VERSION 5.8 ;
BUSBITCHARS "[]" ;
DIVIDERCHAR "/" ;
UNITS
    DATABASE MICRONS 1000 ;
END UNITS

VIA ino_data_cache_via1_2_1000_440_1_2_410_410
  VIARULE via1Array ;
  CUTSIZE 0.19 0.19 ;
  LAYERS Metal1 Via1 Metal2 ;
  CUTSPACING 0.22 0.22 ;
  ENCLOSURE 0.05 0.125 0.005 0.05 ;
  ROWCOL 1 2 ;
END ino_data_cache_via1_2_1000_440_1_2_410_410

VIA ino_data_cache_via2_3_1000_440_1_2_410_410
  VIARULE via2Array ;
  CUTSIZE 0.19 0.19 ;
  LAYERS Metal2 Via2 Metal3 ;
  CUTSPACING 0.22 0.22 ;
  ENCLOSURE 0.005 0.05 0.05 0.005 ;
  ROWCOL 1 2 ;
END ino_data_cache_via2_3_1000_440_1_2_410_410

VIA ino_data_cache_via3_4_1000_440_1_2_410_410
  VIARULE via3Array ;
  CUTSIZE 0.19 0.19 ;
  LAYERS Metal3 Via3 Metal4 ;
  CUTSPACING 0.22 0.22 ;
  ENCLOSURE 0.05 0.005 0.2 0.05 ;
  ROWCOL 1 2 ;
END ino_data_cache_via3_4_1000_440_1_2_410_410

VIA ino_data_cache_via4_5_1000_2000_1_1_840_840
  VIARULE viaTop1Array ;
  CUTSIZE 0.42 0.42 ;
  LAYERS Metal4 TopVia1 TopMetal1 ;
  CUTSPACING 0.42 0.42 ;
  ENCLOSURE 0.29 0.1 0.42 0.79 ;
END ino_data_cache_via4_5_1000_2000_1_1_840_840

VIA ino_data_cache_via4_5_2810_2000_1_2_840_840
  VIARULE viaTop1Array ;
  CUTSIZE 0.42 0.42 ;
  LAYERS Metal4 TopVia1 TopMetal1 ;
  CUTSPACING 0.42 0.42 ;
  ENCLOSURE 0.775 0.79 0.42 0.79 ;
  ROWCOL 1 2 ;
END ino_data_cache_via4_5_2810_2000_1_2_840_840

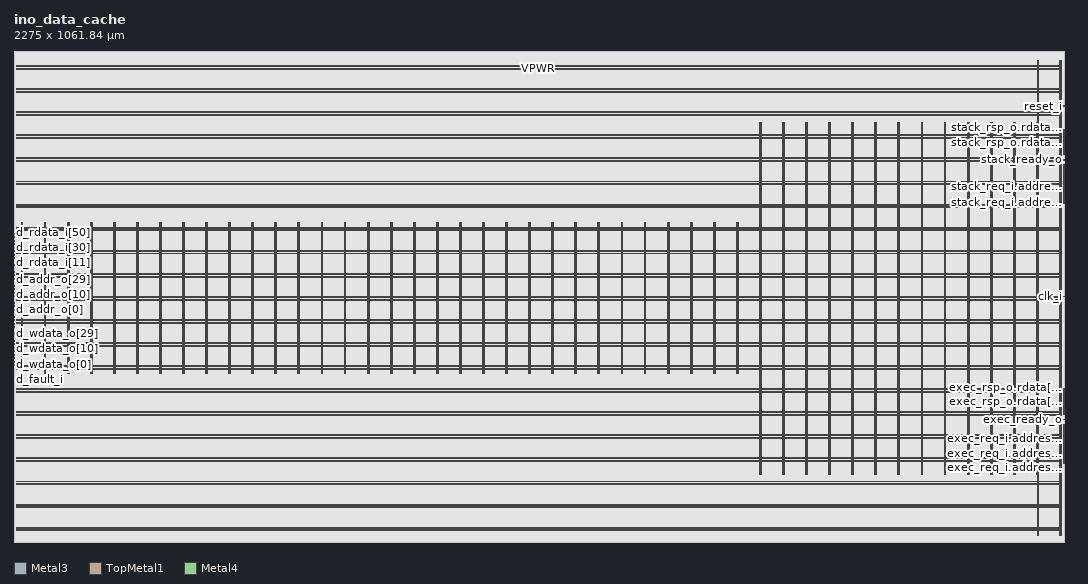
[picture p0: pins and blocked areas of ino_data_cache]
MACRO ino_data_cache
  FOREIGN ino_data_cache 0 0 ;
  CLASS BLOCK ;
  SIZE 2275 BY 1061.84 ;
  PIN clk_i
    DIRECTION INPUT ;
    USE SIGNAL ;
    PORT
      LAYER Metal3 ;
        RECT  2274.6 531.94 2275 532.34 ;
    END
  END clk_i
  PIN d_addr_o[0]
    DIRECTION OUTPUT ;
    USE SIGNAL ;
    PORT
      LAYER Metal3 ;
        RECT  0 502.54 0.4 502.94 ;
    END
  END d_addr_o[0]
  PIN d_addr_o[10]
    DIRECTION OUTPUT ;
    USE SIGNAL ;
    PORT
      LAYER Metal3 ;
        RECT  0 519.34 0.4 519.74 ;
    END
  END d_addr_o[10]
  PIN d_addr_o[11]
    DIRECTION OUTPUT ;
    USE SIGNAL ;
    PORT
      LAYER Metal3 ;
        RECT  0 521.02 0.4 521.42 ;
    END
  END d_addr_o[11]
  PIN d_addr_o[12]
    DIRECTION OUTPUT ;
    USE SIGNAL ;
    PORT
      LAYER Metal3 ;
        RECT  0 522.7 0.4 523.1 ;
    END
  END d_addr_o[12]
  PIN d_addr_o[13]
    DIRECTION OUTPUT ;
    USE SIGNAL ;
    PORT
      LAYER Metal3 ;
        RECT  0 524.38 0.4 524.78 ;
    END
  END d_addr_o[13]
  PIN d_addr_o[14]
    DIRECTION OUTPUT ;
    USE SIGNAL ;
    PORT
      LAYER Metal3 ;
        RECT  0 526.06 0.4 526.46 ;
    END
  END d_addr_o[14]
  PIN d_addr_o[15]
    DIRECTION OUTPUT ;
    USE SIGNAL ;
    PORT
      LAYER Metal3 ;
        RECT  0 527.74 0.4 528.14 ;
    END
  END d_addr_o[15]
  PIN d_addr_o[16]
    DIRECTION OUTPUT ;
    USE SIGNAL ;
    PORT
      LAYER Metal3 ;
        RECT  0 529.42 0.4 529.82 ;
    END
  END d_addr_o[16]
  PIN d_addr_o[17]
    DIRECTION OUTPUT ;
    USE SIGNAL ;
    PORT
      LAYER Metal3 ;
        RECT  0 531.1 0.4 531.5 ;
    END
  END d_addr_o[17]
  PIN d_addr_o[18]
    DIRECTION OUTPUT ;
    USE SIGNAL ;
    PORT
      LAYER Metal3 ;
        RECT  0 532.78 0.4 533.18 ;
    END
  END d_addr_o[18]
  PIN d_addr_o[19]
    DIRECTION OUTPUT ;
    USE SIGNAL ;
    PORT
      LAYER Metal3 ;
        RECT  0 534.46 0.4 534.86 ;
    END
  END d_addr_o[19]
  PIN d_addr_o[1]
    DIRECTION OUTPUT ;
    USE SIGNAL ;
    PORT
      LAYER Metal3 ;
        RECT  0 504.22 0.4 504.62 ;
    END
  END d_addr_o[1]
  PIN d_addr_o[20]
    DIRECTION OUTPUT ;
    USE SIGNAL ;
    PORT
      LAYER Metal3 ;
        RECT  0 536.14 0.4 536.54 ;
    END
  END d_addr_o[20]
  PIN d_addr_o[21]
    DIRECTION OUTPUT ;
    USE SIGNAL ;
    PORT
      LAYER Metal3 ;
        RECT  0 537.82 0.4 538.22 ;
    END
  END d_addr_o[21]
  PIN d_addr_o[22]
    DIRECTION OUTPUT ;
    USE SIGNAL ;
    PORT
      LAYER Metal3 ;
        RECT  0 539.5 0.4 539.9 ;
    END
  END d_addr_o[22]
  PIN d_addr_o[23]
    DIRECTION OUTPUT ;
    USE SIGNAL ;
    PORT
      LAYER Metal3 ;
        RECT  0 541.18 0.4 541.58 ;
    END
  END d_addr_o[23]
  PIN d_addr_o[24]
    DIRECTION OUTPUT ;
    USE SIGNAL ;
    PORT
      LAYER Metal3 ;
        RECT  0 542.86 0.4 543.26 ;
    END
  END d_addr_o[24]
  PIN d_addr_o[25]
    DIRECTION OUTPUT ;
    USE SIGNAL ;
    PORT
      LAYER Metal3 ;
        RECT  0 544.54 0.4 544.94 ;
    END
  END d_addr_o[25]
  PIN d_addr_o[26]
    DIRECTION OUTPUT ;
    USE SIGNAL ;
    PORT
      LAYER Metal3 ;
        RECT  0 546.22 0.4 546.62 ;
    END
  END d_addr_o[26]
  PIN d_addr_o[27]
    DIRECTION OUTPUT ;
    USE SIGNAL ;
    PORT
      LAYER Metal3 ;
        RECT  0 547.9 0.4 548.3 ;
    END
  END d_addr_o[27]
  PIN d_addr_o[28]
    DIRECTION OUTPUT ;
    USE SIGNAL ;
    PORT
      LAYER Metal3 ;
        RECT  0 549.58 0.4 549.98 ;
    END
  END d_addr_o[28]
  PIN d_addr_o[29]
    DIRECTION OUTPUT ;
    USE SIGNAL ;
    PORT
      LAYER Metal3 ;
        RECT  0 551.26 0.4 551.66 ;
    END
  END d_addr_o[29]
  PIN d_addr_o[2]
    DIRECTION OUTPUT ;
    USE SIGNAL ;
    PORT
      LAYER Metal3 ;
        RECT  0 505.9 0.4 506.3 ;
    END
  END d_addr_o[2]
  PIN d_addr_o[30]
    DIRECTION OUTPUT ;
    USE SIGNAL ;
    PORT
      LAYER Metal3 ;
        RECT  0 552.94 0.4 553.34 ;
    END
  END d_addr_o[30]
  PIN d_addr_o[31]
    DIRECTION OUTPUT ;
    USE SIGNAL ;
    PORT
      LAYER Metal3 ;
        RECT  0 554.62 0.4 555.02 ;
    END
  END d_addr_o[31]
  PIN d_addr_o[3]
    DIRECTION OUTPUT ;
    USE SIGNAL ;
    PORT
      LAYER Metal3 ;
        RECT  0 507.58 0.4 507.98 ;
    END
  END d_addr_o[3]
  PIN d_addr_o[4]
    DIRECTION OUTPUT ;
    USE SIGNAL ;
    PORT
      LAYER Metal3 ;
        RECT  0 509.26 0.4 509.66 ;
    END
  END d_addr_o[4]
  PIN d_addr_o[5]
    DIRECTION OUTPUT ;
    USE SIGNAL ;
    PORT
      LAYER Metal3 ;
        RECT  0 510.94 0.4 511.34 ;
    END
  END d_addr_o[5]
  PIN d_addr_o[6]
    DIRECTION OUTPUT ;
    USE SIGNAL ;
    PORT
      LAYER Metal3 ;
        RECT  0 512.62 0.4 513.02 ;
    END
  END d_addr_o[6]
  PIN d_addr_o[7]
    DIRECTION OUTPUT ;
    USE SIGNAL ;
    PORT
      LAYER Metal3 ;
        RECT  0 514.3 0.4 514.7 ;
    END
  END d_addr_o[7]
  PIN d_addr_o[8]
    DIRECTION OUTPUT ;
    USE SIGNAL ;
    PORT
      LAYER Metal3 ;
        RECT  0 515.98 0.4 516.38 ;
    END
  END d_addr_o[8]
  PIN d_addr_o[9]
    DIRECTION OUTPUT ;
    USE SIGNAL ;
    PORT
      LAYER Metal3 ;
        RECT  0 517.66 0.4 518.06 ;
    END
  END d_addr_o[9]
  PIN d_fault_i
    DIRECTION INPUT ;
    USE SIGNAL ;
    PORT
      LAYER Metal3 ;
        RECT  0 369.82 0.4 370.22 ;
    END
  END d_fault_i
  PIN d_rdata_i[0]
    DIRECTION INPUT ;
    USE SIGNAL ;
    PORT
      LAYER Metal3 ;
        RECT  0 569.74 0.4 570.14 ;
    END
  END d_rdata_i[0]
  PIN d_rdata_i[10]
    DIRECTION INPUT ;
    USE SIGNAL ;
    PORT
      LAYER Metal3 ;
        RECT  0 586.54 0.4 586.94 ;
    END
  END d_rdata_i[10]
  PIN d_rdata_i[11]
    DIRECTION INPUT ;
    USE SIGNAL ;
    PORT
      LAYER Metal3 ;
        RECT  0 588.22 0.4 588.62 ;
    END
  END d_rdata_i[11]
  PIN d_rdata_i[12]
    DIRECTION INPUT ;
    USE SIGNAL ;
    PORT
      LAYER Metal3 ;
        RECT  0 589.9 0.4 590.3 ;
    END
  END d_rdata_i[12]
  PIN d_rdata_i[13]
    DIRECTION INPUT ;
    USE SIGNAL ;
    PORT
      LAYER Metal3 ;
        RECT  0 591.58 0.4 591.98 ;
    END
  END d_rdata_i[13]
  PIN d_rdata_i[14]
    DIRECTION INPUT ;
    USE SIGNAL ;
    PORT
      LAYER Metal3 ;
        RECT  0 593.26 0.4 593.66 ;
    END
  END d_rdata_i[14]
  PIN d_rdata_i[15]
    DIRECTION INPUT ;
    USE SIGNAL ;
    PORT
      LAYER Metal3 ;
        RECT  0 594.94 0.4 595.34 ;
    END
  END d_rdata_i[15]
  PIN d_rdata_i[16]
    DIRECTION INPUT ;
    USE SIGNAL ;
    PORT
      LAYER Metal3 ;
        RECT  0 596.62 0.4 597.02 ;
    END
  END d_rdata_i[16]
  PIN d_rdata_i[17]
    DIRECTION INPUT ;
    USE SIGNAL ;
    PORT
      LAYER Metal3 ;
        RECT  0 598.3 0.4 598.7 ;
    END
  END d_rdata_i[17]
  PIN d_rdata_i[18]
    DIRECTION INPUT ;
    USE SIGNAL ;
    PORT
      LAYER Metal3 ;
        RECT  0 599.98 0.4 600.38 ;
    END
  END d_rdata_i[18]
  PIN d_rdata_i[19]
    DIRECTION INPUT ;
    USE SIGNAL ;
    PORT
      LAYER Metal3 ;
        RECT  0 601.66 0.4 602.06 ;
    END
  END d_rdata_i[19]
  PIN d_rdata_i[1]
    DIRECTION INPUT ;
    USE SIGNAL ;
    PORT
      LAYER Metal3 ;
        RECT  0 571.42 0.4 571.82 ;
    END
  END d_rdata_i[1]
  PIN d_rdata_i[20]
    DIRECTION INPUT ;
    USE SIGNAL ;
    PORT
      LAYER Metal3 ;
        RECT  0 603.34 0.4 603.74 ;
    END
  END d_rdata_i[20]
  PIN d_rdata_i[21]
    DIRECTION INPUT ;
    USE SIGNAL ;
    PORT
      LAYER Metal3 ;
        RECT  0 605.02 0.4 605.42 ;
    END
  END d_rdata_i[21]
  PIN d_rdata_i[22]
    DIRECTION INPUT ;
    USE SIGNAL ;
    PORT
      LAYER Metal3 ;
        RECT  0 606.7 0.4 607.1 ;
    END
  END d_rdata_i[22]
  PIN d_rdata_i[23]
    DIRECTION INPUT ;
    USE SIGNAL ;
    PORT
      LAYER Metal3 ;
        RECT  0 608.38 0.4 608.78 ;
    END
  END d_rdata_i[23]
  PIN d_rdata_i[24]
    DIRECTION INPUT ;
    USE SIGNAL ;
    PORT
      LAYER Metal3 ;
        RECT  0 610.06 0.4 610.46 ;
    END
  END d_rdata_i[24]
  PIN d_rdata_i[25]
    DIRECTION INPUT ;
    USE SIGNAL ;
    PORT
      LAYER Metal3 ;
        RECT  0 611.74 0.4 612.14 ;
    END
  END d_rdata_i[25]
  PIN d_rdata_i[26]
    DIRECTION INPUT ;
    USE SIGNAL ;
    PORT
      LAYER Metal3 ;
        RECT  0 613.42 0.4 613.82 ;
    END
  END d_rdata_i[26]
  PIN d_rdata_i[27]
    DIRECTION INPUT ;
    USE SIGNAL ;
    PORT
      LAYER Metal3 ;
        RECT  0 615.1 0.4 615.5 ;
    END
  END d_rdata_i[27]
  PIN d_rdata_i[28]
    DIRECTION INPUT ;
    USE SIGNAL ;
    PORT
      LAYER Metal3 ;
        RECT  0 616.78 0.4 617.18 ;
    END
  END d_rdata_i[28]
  PIN d_rdata_i[29]
    DIRECTION INPUT ;
    USE SIGNAL ;
    PORT
      LAYER Metal3 ;
        RECT  0 618.46 0.4 618.86 ;
    END
  END d_rdata_i[29]
  PIN d_rdata_i[2]
    DIRECTION INPUT ;
    USE SIGNAL ;
    PORT
      LAYER Metal3 ;
        RECT  0 573.1 0.4 573.5 ;
    END
  END d_rdata_i[2]
  PIN d_rdata_i[30]
    DIRECTION INPUT ;
    USE SIGNAL ;
    PORT
      LAYER Metal3 ;
        RECT  0 620.14 0.4 620.54 ;
    END
  END d_rdata_i[30]
  PIN d_rdata_i[31]
    DIRECTION INPUT ;
    USE SIGNAL ;
    PORT
      LAYER Metal3 ;
        RECT  0 621.82 0.4 622.22 ;
    END
  END d_rdata_i[31]
  PIN d_rdata_i[32]
    DIRECTION INPUT ;
    USE SIGNAL ;
    PORT
      LAYER Metal3 ;
        RECT  0 623.5 0.4 623.9 ;
    END
  END d_rdata_i[32]
  PIN d_rdata_i[33]
    DIRECTION INPUT ;
    USE SIGNAL ;
    PORT
      LAYER Metal3 ;
        RECT  0 625.18 0.4 625.58 ;
    END
  END d_rdata_i[33]
  PIN d_rdata_i[34]
    DIRECTION INPUT ;
    USE SIGNAL ;
    PORT
      LAYER Metal3 ;
        RECT  0 626.86 0.4 627.26 ;
    END
  END d_rdata_i[34]
  PIN d_rdata_i[35]
    DIRECTION INPUT ;
    USE SIGNAL ;
    PORT
      LAYER Metal3 ;
        RECT  0 628.54 0.4 628.94 ;
    END
  END d_rdata_i[35]
  PIN d_rdata_i[36]
    DIRECTION INPUT ;
    USE SIGNAL ;
    PORT
      LAYER Metal3 ;
        RECT  0 630.22 0.4 630.62 ;
    END
  END d_rdata_i[36]
  PIN d_rdata_i[37]
    DIRECTION INPUT ;
    USE SIGNAL ;
    PORT
      LAYER Metal3 ;
        RECT  0 631.9 0.4 632.3 ;
    END
  END d_rdata_i[37]
  PIN d_rdata_i[38]
    DIRECTION INPUT ;
    USE SIGNAL ;
    PORT
      LAYER Metal3 ;
        RECT  0 633.58 0.4 633.98 ;
    END
  END d_rdata_i[38]
  PIN d_rdata_i[39]
    DIRECTION INPUT ;
    USE SIGNAL ;
    PORT
      LAYER Metal3 ;
        RECT  0 635.26 0.4 635.66 ;
    END
  END d_rdata_i[39]
  PIN d_rdata_i[3]
    DIRECTION INPUT ;
    USE SIGNAL ;
    PORT
      LAYER Metal3 ;
        RECT  0 574.78 0.4 575.18 ;
    END
  END d_rdata_i[3]
  PIN d_rdata_i[40]
    DIRECTION INPUT ;
    USE SIGNAL ;
    PORT
      LAYER Metal3 ;
        RECT  0 636.94 0.4 637.34 ;
    END
  END d_rdata_i[40]
  PIN d_rdata_i[41]
    DIRECTION INPUT ;
    USE SIGNAL ;
    PORT
      LAYER Metal3 ;
        RECT  0 638.62 0.4 639.02 ;
    END
  END d_rdata_i[41]
  PIN d_rdata_i[42]
    DIRECTION INPUT ;
    USE SIGNAL ;
    PORT
      LAYER Metal3 ;
        RECT  0 640.3 0.4 640.7 ;
    END
  END d_rdata_i[42]
  PIN d_rdata_i[43]
    DIRECTION INPUT ;
    USE SIGNAL ;
    PORT
      LAYER Metal3 ;
        RECT  0 641.98 0.4 642.38 ;
    END
  END d_rdata_i[43]
  PIN d_rdata_i[44]
    DIRECTION INPUT ;
    USE SIGNAL ;
    PORT
      LAYER Metal3 ;
        RECT  0 643.66 0.4 644.06 ;
    END
  END d_rdata_i[44]
  PIN d_rdata_i[45]
    DIRECTION INPUT ;
    USE SIGNAL ;
    PORT
      LAYER Metal3 ;
        RECT  0 645.34 0.4 645.74 ;
    END
  END d_rdata_i[45]
  PIN d_rdata_i[46]
    DIRECTION INPUT ;
    USE SIGNAL ;
    PORT
      LAYER Metal3 ;
        RECT  0 647.02 0.4 647.42 ;
    END
  END d_rdata_i[46]
  PIN d_rdata_i[47]
    DIRECTION INPUT ;
    USE SIGNAL ;
    PORT
      LAYER Metal3 ;
        RECT  0 648.7 0.4 649.1 ;
    END
  END d_rdata_i[47]
  PIN d_rdata_i[48]
    DIRECTION INPUT ;
    USE SIGNAL ;
    PORT
      LAYER Metal3 ;
        RECT  0 650.38 0.4 650.78 ;
    END
  END d_rdata_i[48]
  PIN d_rdata_i[49]
    DIRECTION INPUT ;
    USE SIGNAL ;
    PORT
      LAYER Metal3 ;
        RECT  0 652.06 0.4 652.46 ;
    END
  END d_rdata_i[49]
  PIN d_rdata_i[4]
    DIRECTION INPUT ;
    USE SIGNAL ;
    PORT
      LAYER Metal3 ;
        RECT  0 576.46 0.4 576.86 ;
    END
  END d_rdata_i[4]
  PIN d_rdata_i[50]
    DIRECTION INPUT ;
    USE SIGNAL ;
    PORT
      LAYER Metal3 ;
        RECT  0 653.74 0.4 654.14 ;
    END
  END d_rdata_i[50]
  PIN d_rdata_i[51]
    DIRECTION INPUT ;
    USE SIGNAL ;
    PORT
      LAYER Metal3 ;
        RECT  0 655.42 0.4 655.82 ;
    END
  END d_rdata_i[51]
  PIN d_rdata_i[52]
    DIRECTION INPUT ;
    USE SIGNAL ;
    PORT
      LAYER Metal3 ;
        RECT  0 657.1 0.4 657.5 ;
    END
  END d_rdata_i[52]
  PIN d_rdata_i[53]
    DIRECTION INPUT ;
    USE SIGNAL ;
    PORT
      LAYER Metal3 ;
        RECT  0 658.78 0.4 659.18 ;
    END
  END d_rdata_i[53]
  PIN d_rdata_i[54]
    DIRECTION INPUT ;
    USE SIGNAL ;
    PORT
      LAYER Metal3 ;
        RECT  0 660.46 0.4 660.86 ;
    END
  END d_rdata_i[54]
  PIN d_rdata_i[55]
    DIRECTION INPUT ;
    USE SIGNAL ;
    PORT
      LAYER Metal3 ;
        RECT  0 662.14 0.4 662.54 ;
    END
  END d_rdata_i[55]
  PIN d_rdata_i[56]
    DIRECTION INPUT ;
    USE SIGNAL ;
    PORT
      LAYER Metal3 ;
        RECT  0 663.82 0.4 664.22 ;
    END
  END d_rdata_i[56]
  PIN d_rdata_i[57]
    DIRECTION INPUT ;
    USE SIGNAL ;
    PORT
      LAYER Metal3 ;
        RECT  0 665.5 0.4 665.9 ;
    END
  END d_rdata_i[57]
  PIN d_rdata_i[58]
    DIRECTION INPUT ;
    USE SIGNAL ;
    PORT
      LAYER Metal3 ;
        RECT  0 667.18 0.4 667.58 ;
    END
  END d_rdata_i[58]
  PIN d_rdata_i[59]
    DIRECTION INPUT ;
    USE SIGNAL ;
    PORT
      LAYER Metal3 ;
        RECT  0 668.86 0.4 669.26 ;
    END
  END d_rdata_i[59]
  PIN d_rdata_i[5]
    DIRECTION INPUT ;
    USE SIGNAL ;
    PORT
      LAYER Metal3 ;
        RECT  0 578.14 0.4 578.54 ;
    END
  END d_rdata_i[5]
  PIN d_rdata_i[60]
    DIRECTION INPUT ;
    USE SIGNAL ;
    PORT
      LAYER Metal3 ;
        RECT  0 670.54 0.4 670.94 ;
    END
  END d_rdata_i[60]
  PIN d_rdata_i[61]
    DIRECTION INPUT ;
    USE SIGNAL ;
    PORT
      LAYER Metal3 ;
        RECT  0 672.22 0.4 672.62 ;
    END
  END d_rdata_i[61]
  PIN d_rdata_i[62]
    DIRECTION INPUT ;
    USE SIGNAL ;
    PORT
      LAYER Metal3 ;
        RECT  0 673.9 0.4 674.3 ;
    END
  END d_rdata_i[62]
  PIN d_rdata_i[63]
    DIRECTION INPUT ;
    USE SIGNAL ;
    PORT
      LAYER Metal3 ;
        RECT  0 675.58 0.4 675.98 ;
    END
  END d_rdata_i[63]
  PIN d_rdata_i[6]
    DIRECTION INPUT ;
    USE SIGNAL ;
    PORT
      LAYER Metal3 ;
        RECT  0 579.82 0.4 580.22 ;
    END
  END d_rdata_i[6]
  PIN d_rdata_i[7]
    DIRECTION INPUT ;
    USE SIGNAL ;
    PORT
      LAYER Metal3 ;
        RECT  0 581.5 0.4 581.9 ;
    END
  END d_rdata_i[7]
  PIN d_rdata_i[8]
    DIRECTION INPUT ;
    USE SIGNAL ;
    PORT
      LAYER Metal3 ;
        RECT  0 583.18 0.4 583.58 ;
    END
  END d_rdata_i[8]
  PIN d_rdata_i[9]
    DIRECTION INPUT ;
    USE SIGNAL ;
    PORT
      LAYER Metal3 ;
        RECT  0 584.86 0.4 585.26 ;
    END
  END d_rdata_i[9]
  PIN d_ready_i
    DIRECTION INPUT ;
    USE SIGNAL ;
    PORT
      LAYER Metal3 ;
        RECT  0 566.38 0.4 566.78 ;
    END
  END d_ready_i
  PIN d_req_o
    DIRECTION OUTPUT ;
    USE SIGNAL ;
    PORT
      LAYER Metal3 ;
        RECT  0 381.58 0.4 381.98 ;
    END
  END d_req_o
  PIN d_rvalid_i
    DIRECTION INPUT ;
    USE SIGNAL ;
    PORT
      LAYER Metal3 ;
        RECT  0 568.06 0.4 568.46 ;
    END
  END d_rvalid_i
  PIN d_wdata_o[0]
    DIRECTION OUTPUT ;
    USE SIGNAL ;
    PORT
      LAYER Metal3 ;
        RECT  0 384.94 0.4 385.34 ;
    END
  END d_wdata_o[0]
  PIN d_wdata_o[10]
    DIRECTION OUTPUT ;
    USE SIGNAL ;
    PORT
      LAYER Metal3 ;
        RECT  0 401.74 0.4 402.14 ;
    END
  END d_wdata_o[10]
  PIN d_wdata_o[11]
    DIRECTION OUTPUT ;
    USE SIGNAL ;
    PORT
      LAYER Metal3 ;
        RECT  0 403.42 0.4 403.82 ;
    END
  END d_wdata_o[11]
  PIN d_wdata_o[12]
    DIRECTION OUTPUT ;
    USE SIGNAL ;
    PORT
      LAYER Metal3 ;
        RECT  0 405.1 0.4 405.5 ;
    END
  END d_wdata_o[12]
  PIN d_wdata_o[13]
    DIRECTION OUTPUT ;
    USE SIGNAL ;
    PORT
      LAYER Metal3 ;
        RECT  0 406.78 0.4 407.18 ;
    END
  END d_wdata_o[13]
  PIN d_wdata_o[14]
    DIRECTION OUTPUT ;
    USE SIGNAL ;
    PORT
      LAYER Metal3 ;
        RECT  0 408.46 0.4 408.86 ;
    END
  END d_wdata_o[14]
  PIN d_wdata_o[15]
    DIRECTION OUTPUT ;
    USE SIGNAL ;
    PORT
      LAYER Metal3 ;
        RECT  0 410.14 0.4 410.54 ;
    END
  END d_wdata_o[15]
  PIN d_wdata_o[16]
    DIRECTION OUTPUT ;
    USE SIGNAL ;
    PORT
      LAYER Metal3 ;
        RECT  0 411.82 0.4 412.22 ;
    END
  END d_wdata_o[16]
  PIN d_wdata_o[17]
    DIRECTION OUTPUT ;
    USE SIGNAL ;
    PORT
      LAYER Metal3 ;
        RECT  0 413.5 0.4 413.9 ;
    END
  END d_wdata_o[17]
  PIN d_wdata_o[18]
    DIRECTION OUTPUT ;
    USE SIGNAL ;
    PORT
      LAYER Metal3 ;
        RECT  0 415.18 0.4 415.58 ;
    END
  END d_wdata_o[18]
  PIN d_wdata_o[19]
    DIRECTION OUTPUT ;
    USE SIGNAL ;
    PORT
      LAYER Metal3 ;
        RECT  0 416.86 0.4 417.26 ;
    END
  END d_wdata_o[19]
  PIN d_wdata_o[1]
    DIRECTION OUTPUT ;
    USE SIGNAL ;
    PORT
      LAYER Metal3 ;
        RECT  0 386.62 0.4 387.02 ;
    END
  END d_wdata_o[1]
  PIN d_wdata_o[20]
    DIRECTION OUTPUT ;
    USE SIGNAL ;
    PORT
      LAYER Metal3 ;
        RECT  0 418.54 0.4 418.94 ;
    END
  END d_wdata_o[20]
  PIN d_wdata_o[21]
    DIRECTION OUTPUT ;
    USE SIGNAL ;
    PORT
      LAYER Metal3 ;
        RECT  0 420.22 0.4 420.62 ;
    END
  END d_wdata_o[21]
  PIN d_wdata_o[22]
    DIRECTION OUTPUT ;
    USE SIGNAL ;
    PORT
      LAYER Metal3 ;
        RECT  0 421.9 0.4 422.3 ;
    END
  END d_wdata_o[22]
  PIN d_wdata_o[23]
    DIRECTION OUTPUT ;
    USE SIGNAL ;
    PORT
      LAYER Metal3 ;
        RECT  0 423.58 0.4 423.98 ;
    END
  END d_wdata_o[23]
  PIN d_wdata_o[24]
    DIRECTION OUTPUT ;
    USE SIGNAL ;
    PORT
      LAYER Metal3 ;
        RECT  0 425.26 0.4 425.66 ;
    END
  END d_wdata_o[24]
  PIN d_wdata_o[25]
    DIRECTION OUTPUT ;
    USE SIGNAL ;
    PORT
      LAYER Metal3 ;
        RECT  0 426.94 0.4 427.34 ;
    END
  END d_wdata_o[25]
  PIN d_wdata_o[26]
    DIRECTION OUTPUT ;
    USE SIGNAL ;
    PORT
      LAYER Metal3 ;
        RECT  0 428.62 0.4 429.02 ;
    END
  END d_wdata_o[26]
  PIN d_wdata_o[27]
    DIRECTION OUTPUT ;
    USE SIGNAL ;
    PORT
      LAYER Metal3 ;
        RECT  0 430.3 0.4 430.7 ;
    END
  END d_wdata_o[27]
  PIN d_wdata_o[28]
    DIRECTION OUTPUT ;
    USE SIGNAL ;
    PORT
      LAYER Metal3 ;
        RECT  0 431.98 0.4 432.38 ;
    END
  END d_wdata_o[28]
  PIN d_wdata_o[29]
    DIRECTION OUTPUT ;
    USE SIGNAL ;
    PORT
      LAYER Metal3 ;
        RECT  0 433.66 0.4 434.06 ;
    END
  END d_wdata_o[29]
  PIN d_wdata_o[2]
    DIRECTION OUTPUT ;
    USE SIGNAL ;
    PORT
      LAYER Metal3 ;
        RECT  0 388.3 0.4 388.7 ;
    END
  END d_wdata_o[2]
  PIN d_wdata_o[30]
    DIRECTION OUTPUT ;
    USE SIGNAL ;
    PORT
      LAYER Metal3 ;
        RECT  0 435.34 0.4 435.74 ;
    END
  END d_wdata_o[30]
  PIN d_wdata_o[31]
    DIRECTION OUTPUT ;
    USE SIGNAL ;
    PORT
      LAYER Metal3 ;
        RECT  0 437.02 0.4 437.42 ;
    END
  END d_wdata_o[31]
  PIN d_wdata_o[32]
    DIRECTION OUTPUT ;
    USE SIGNAL ;
    PORT
      LAYER Metal3 ;
        RECT  0 438.7 0.4 439.1 ;
    END
  END d_wdata_o[32]
  PIN d_wdata_o[33]
    DIRECTION OUTPUT ;
    USE SIGNAL ;
    PORT
      LAYER Metal3 ;
        RECT  0 440.38 0.4 440.78 ;
    END
  END d_wdata_o[33]
  PIN d_wdata_o[34]
    DIRECTION OUTPUT ;
    USE SIGNAL ;
    PORT
      LAYER Metal3 ;
        RECT  0 442.06 0.4 442.46 ;
    END
  END d_wdata_o[34]
  PIN d_wdata_o[35]
    DIRECTION OUTPUT ;
    USE SIGNAL ;
    PORT
      LAYER Metal3 ;
        RECT  0 443.74 0.4 444.14 ;
    END
  END d_wdata_o[35]
  PIN d_wdata_o[36]
    DIRECTION OUTPUT ;
    USE SIGNAL ;
    PORT
      LAYER Metal3 ;
        RECT  0 445.42 0.4 445.82 ;
    END
  END d_wdata_o[36]
  PIN d_wdata_o[37]
    DIRECTION OUTPUT ;
    USE SIGNAL ;
    PORT
      LAYER Metal3 ;
        RECT  0 447.1 0.4 447.5 ;
    END
  END d_wdata_o[37]
  PIN d_wdata_o[38]
    DIRECTION OUTPUT ;
    USE SIGNAL ;
    PORT
      LAYER Metal3 ;
        RECT  0 448.78 0.4 449.18 ;
    END
  END d_wdata_o[38]
  PIN d_wdata_o[39]
    DIRECTION OUTPUT ;
    USE SIGNAL ;
    PORT
      LAYER Metal3 ;
        RECT  0 450.46 0.4 450.86 ;
    END
  END d_wdata_o[39]
  PIN d_wdata_o[3]
    DIRECTION OUTPUT ;
    USE SIGNAL ;
    PORT
      LAYER Metal3 ;
        RECT  0 389.98 0.4 390.38 ;
    END
  END d_wdata_o[3]
  PIN d_wdata_o[40]
    DIRECTION OUTPUT ;
    USE SIGNAL ;
    PORT
      LAYER Metal3 ;
        RECT  0 452.14 0.4 452.54 ;
    END
  END d_wdata_o[40]
  PIN d_wdata_o[41]
    DIRECTION OUTPUT ;
    USE SIGNAL ;
    PORT
      LAYER Metal3 ;
        RECT  0 453.82 0.4 454.22 ;
    END
  END d_wdata_o[41]
  PIN d_wdata_o[42]
    DIRECTION OUTPUT ;
    USE SIGNAL ;
    PORT
      LAYER Metal3 ;
        RECT  0 455.5 0.4 455.9 ;
    END
  END d_wdata_o[42]
  PIN d_wdata_o[43]
    DIRECTION OUTPUT ;
    USE SIGNAL ;
    PORT
      LAYER Metal3 ;
        RECT  0 457.18 0.4 457.58 ;
    END
  END d_wdata_o[43]
  PIN d_wdata_o[44]
    DIRECTION OUTPUT ;
    USE SIGNAL ;
    PORT
      LAYER Metal3 ;
        RECT  0 458.86 0.4 459.26 ;
    END
  END d_wdata_o[44]
  PIN d_wdata_o[45]
    DIRECTION OUTPUT ;
    USE SIGNAL ;
    PORT
      LAYER Metal3 ;
        RECT  0 460.54 0.4 460.94 ;
    END
  END d_wdata_o[45]
  PIN d_wdata_o[46]
    DIRECTION OUTPUT ;
    USE SIGNAL ;
    PORT
      LAYER Metal3 ;
        RECT  0 462.22 0.4 462.62 ;
    END
  END d_wdata_o[46]
  PIN d_wdata_o[47]
    DIRECTION OUTPUT ;
    USE SIGNAL ;
    PORT
      LAYER Metal3 ;
        RECT  0 463.9 0.4 464.3 ;
    END
  END d_wdata_o[47]
  PIN d_wdata_o[48]
    DIRECTION OUTPUT ;
    USE SIGNAL ;
    PORT
      LAYER Metal3 ;
        RECT  0 465.58 0.4 465.98 ;
    END
  END d_wdata_o[48]
  PIN d_wdata_o[49]
    DIRECTION OUTPUT ;
    USE SIGNAL ;
    PORT
      LAYER Metal3 ;
        RECT  0 467.26 0.4 467.66 ;
    END
  END d_wdata_o[49]
  PIN d_wdata_o[4]
    DIRECTION OUTPUT ;
    USE SIGNAL ;
    PORT
      LAYER Metal3 ;
        RECT  0 391.66 0.4 392.06 ;
    END
  END d_wdata_o[4]
  PIN d_wdata_o[50]
    DIRECTION OUTPUT ;
    USE SIGNAL ;
    PORT
      LAYER Metal3 ;
        RECT  0 468.94 0.4 469.34 ;
    END
  END d_wdata_o[50]
  PIN d_wdata_o[51]
    DIRECTION OUTPUT ;
    USE SIGNAL ;
    PORT
      LAYER Metal3 ;
        RECT  0 470.62 0.4 471.02 ;
    END
  END d_wdata_o[51]
  PIN d_wdata_o[52]
    DIRECTION OUTPUT ;
    USE SIGNAL ;
    PORT
      LAYER Metal3 ;
        RECT  0 472.3 0.4 472.7 ;
    END
  END d_wdata_o[52]
  PIN d_wdata_o[53]
    DIRECTION OUTPUT ;
    USE SIGNAL ;
    PORT
      LAYER Metal3 ;
        RECT  0 473.98 0.4 474.38 ;
    END
  END d_wdata_o[53]
  PIN d_wdata_o[54]
    DIRECTION OUTPUT ;
    USE SIGNAL ;
    PORT
      LAYER Metal3 ;
        RECT  0 475.66 0.4 476.06 ;
    END
  END d_wdata_o[54]
  PIN d_wdata_o[55]
    DIRECTION OUTPUT ;
    USE SIGNAL ;
    PORT
      LAYER Metal3 ;
        RECT  0 477.34 0.4 477.74 ;
    END
  END d_wdata_o[55]
  PIN d_wdata_o[56]
    DIRECTION OUTPUT ;
    USE SIGNAL ;
    PORT
      LAYER Metal3 ;
        RECT  0 479.02 0.4 479.42 ;
    END
  END d_wdata_o[56]
  PIN d_wdata_o[57]
    DIRECTION OUTPUT ;
    USE SIGNAL ;
    PORT
      LAYER Metal3 ;
        RECT  0 480.7 0.4 481.1 ;
    END
  END d_wdata_o[57]
  PIN d_wdata_o[58]
    DIRECTION OUTPUT ;
    USE SIGNAL ;
    PORT
      LAYER Metal3 ;
        RECT  0 482.38 0.4 482.78 ;
    END
  END d_wdata_o[58]
  PIN d_wdata_o[59]
    DIRECTION OUTPUT ;
    USE SIGNAL ;
    PORT
      LAYER Metal3 ;
        RECT  0 484.06 0.4 484.46 ;
    END
  END d_wdata_o[59]
  PIN d_wdata_o[5]
    DIRECTION OUTPUT ;
    USE SIGNAL ;
    PORT
      LAYER Metal3 ;
        RECT  0 393.34 0.4 393.74 ;
    END
  END d_wdata_o[5]
  PIN d_wdata_o[60]
    DIRECTION OUTPUT ;
    USE SIGNAL ;
    PORT
      LAYER Metal3 ;
        RECT  0 485.74 0.4 486.14 ;
    END
  END d_wdata_o[60]
  PIN d_wdata_o[61]
    DIRECTION OUTPUT ;
    USE SIGNAL ;
    PORT
      LAYER Metal3 ;
        RECT  0 487.42 0.4 487.82 ;
    END
  END d_wdata_o[61]
  PIN d_wdata_o[62]
    DIRECTION OUTPUT ;
    USE SIGNAL ;
    PORT
      LAYER Metal3 ;
        RECT  0 489.1 0.4 489.5 ;
    END
  END d_wdata_o[62]
  PIN d_wdata_o[63]
    DIRECTION OUTPUT ;
    USE SIGNAL ;
    PORT
      LAYER Metal3 ;
        RECT  0 490.78 0.4 491.18 ;
    END
  END d_wdata_o[63]
  PIN d_wdata_o[6]
    DIRECTION OUTPUT ;
    USE SIGNAL ;
    PORT
      LAYER Metal3 ;
        RECT  0 395.02 0.4 395.42 ;
    END
  END d_wdata_o[6]
  PIN d_wdata_o[7]
    DIRECTION OUTPUT ;
    USE SIGNAL ;
    PORT
      LAYER Metal3 ;
        RECT  0 396.7 0.4 397.1 ;
    END
  END d_wdata_o[7]
  PIN d_wdata_o[8]
    DIRECTION OUTPUT ;
    USE SIGNAL ;
    PORT
      LAYER Metal3 ;
        RECT  0 398.38 0.4 398.78 ;
    END
  END d_wdata_o[8]
  PIN d_wdata_o[9]
    DIRECTION OUTPUT ;
    USE SIGNAL ;
    PORT
      LAYER Metal3 ;
        RECT  0 400.06 0.4 400.46 ;
    END
  END d_wdata_o[9]
  PIN d_write_o
    DIRECTION OUTPUT ;
    USE SIGNAL ;
    PORT
      LAYER Metal3 ;
        RECT  0 383.26 0.4 383.66 ;
    END
  END d_write_o
  PIN exec_ready_o
    DIRECTION OUTPUT ;
    USE SIGNAL ;
    PORT
      LAYER Metal3 ;
        RECT  2274.6 265.66 2275 266.06 ;
    END
  END exec_ready_o
  PIN exec_req_i.address[0]
    DIRECTION INPUT ;
    USE SIGNAL ;
    PORT
      LAYER Metal3 ;
        RECT  2274.6 173.26 2275 173.66 ;
    END
  END exec_req_i.address[0]
  PIN exec_req_i.address[10]
    DIRECTION INPUT ;
    USE SIGNAL ;
    PORT
      LAYER Metal3 ;
        RECT  2274.6 191.74 2275 192.14 ;
    END
  END exec_req_i.address[10]
  PIN exec_req_i.address[11]
    DIRECTION INPUT ;
    USE SIGNAL ;
    PORT
      LAYER Metal3 ;
        RECT  2274.6 193.42 2275 193.82 ;
    END
  END exec_req_i.address[11]
  PIN exec_req_i.address[12]
    DIRECTION INPUT ;
    USE SIGNAL ;
    PORT
      LAYER Metal3 ;
        RECT  2274.6 195.1 2275 195.5 ;
    END
  END exec_req_i.address[12]
  PIN exec_req_i.address[13]
    DIRECTION INPUT ;
    USE SIGNAL ;
    PORT
      LAYER Metal3 ;
        RECT  2274.6 196.78 2275 197.18 ;
    END
  END exec_req_i.address[13]
  PIN exec_req_i.address[14]
    DIRECTION INPUT ;
    USE SIGNAL ;
    PORT
      LAYER Metal3 ;
        RECT  2274.6 198.46 2275 198.86 ;
    END
  END exec_req_i.address[14]
  PIN exec_req_i.address[15]
    DIRECTION INPUT ;
    USE SIGNAL ;
    PORT
      LAYER Metal3 ;
        RECT  2274.6 200.14 2275 200.54 ;
    END
  END exec_req_i.address[15]
  PIN exec_req_i.address[16]
    DIRECTION INPUT ;
    USE SIGNAL ;
    PORT
      LAYER Metal3 ;
        RECT  2274.6 201.82 2275 202.22 ;
    END
  END exec_req_i.address[16]
  PIN exec_req_i.address[17]
    DIRECTION INPUT ;
    USE SIGNAL ;
    PORT
      LAYER Metal3 ;
        RECT  2274.6 203.5 2275 203.9 ;
    END
  END exec_req_i.address[17]
  PIN exec_req_i.address[18]
    DIRECTION INPUT ;
    USE SIGNAL ;
    PORT
      LAYER Metal3 ;
        RECT  2274.6 205.18 2275 205.58 ;
    END
  END exec_req_i.address[18]
  PIN exec_req_i.address[19]
    DIRECTION INPUT ;
    USE SIGNAL ;
    PORT
      LAYER Metal3 ;
        RECT  2274.6 206.86 2275 207.26 ;
    END
  END exec_req_i.address[19]
  PIN exec_req_i.address[1]
    DIRECTION INPUT ;
    USE SIGNAL ;
    PORT
      LAYER Metal3 ;
        RECT  2274.6 175.78 2275 176.18 ;
    END
  END exec_req_i.address[1]
  PIN exec_req_i.address[20]
    DIRECTION INPUT ;
    USE SIGNAL ;
    PORT
      LAYER Metal3 ;
        RECT  2274.6 208.54 2275 208.94 ;
    END
  END exec_req_i.address[20]
  PIN exec_req_i.address[21]
    DIRECTION INPUT ;
    USE SIGNAL ;
    PORT
      LAYER Metal3 ;
        RECT  2274.6 210.22 2275 210.62 ;
    END
  END exec_req_i.address[21]
  PIN exec_req_i.address[22]
    DIRECTION INPUT ;
    USE SIGNAL ;
    PORT
      LAYER Metal3 ;
        RECT  2274.6 211.9 2275 212.3 ;
    END
  END exec_req_i.address[22]
  PIN exec_req_i.address[23]
    DIRECTION INPUT ;
    USE SIGNAL ;
    PORT
      LAYER Metal3 ;
        RECT  2274.6 213.58 2275 213.98 ;
    END
  END exec_req_i.address[23]
  PIN exec_req_i.address[24]
    DIRECTION INPUT ;
    USE SIGNAL ;
    PORT
      LAYER Metal3 ;
        RECT  2274.6 215.26 2275 215.66 ;
    END
  END exec_req_i.address[24]
  PIN exec_req_i.address[25]
    DIRECTION INPUT ;
    USE SIGNAL ;
    PORT
      LAYER Metal3 ;
        RECT  2274.6 216.94 2275 217.34 ;
    END
  END exec_req_i.address[25]
  PIN exec_req_i.address[26]
    DIRECTION INPUT ;
    USE SIGNAL ;
    PORT
      LAYER Metal3 ;
        RECT  2274.6 218.62 2275 219.02 ;
    END
  END exec_req_i.address[26]
  PIN exec_req_i.address[27]
    DIRECTION INPUT ;
    USE SIGNAL ;
    PORT
      LAYER Metal3 ;
        RECT  2274.6 220.3 2275 220.7 ;
    END
  END exec_req_i.address[27]
  PIN exec_req_i.address[28]
    DIRECTION INPUT ;
    USE SIGNAL ;
    PORT
      LAYER Metal3 ;
        RECT  2274.6 221.98 2275 222.38 ;
    END
  END exec_req_i.address[28]
  PIN exec_req_i.address[29]
    DIRECTION INPUT ;
    USE SIGNAL ;
    PORT
      LAYER Metal3 ;
        RECT  2274.6 223.66 2275 224.06 ;
    END
  END exec_req_i.address[29]
  PIN exec_req_i.address[2]
    DIRECTION INPUT ;
    USE SIGNAL ;
    PORT
      LAYER Metal3 ;
        RECT  2274.6 178.3 2275 178.7 ;
    END
  END exec_req_i.address[2]
  PIN exec_req_i.address[30]
    DIRECTION INPUT ;
    USE SIGNAL ;
    PORT
      LAYER Metal3 ;
        RECT  2274.6 225.34 2275 225.74 ;
    END
  END exec_req_i.address[30]
  PIN exec_req_i.address[31]
    DIRECTION INPUT ;
    USE SIGNAL ;
    PORT
      LAYER Metal3 ;
        RECT  2274.6 227.02 2275 227.42 ;
    END
  END exec_req_i.address[31]
  PIN exec_req_i.address[3]
    DIRECTION INPUT ;
    USE SIGNAL ;
    PORT
      LAYER Metal3 ;
        RECT  2274.6 179.98 2275 180.38 ;
    END
  END exec_req_i.address[3]
  PIN exec_req_i.address[4]
    DIRECTION INPUT ;
    USE SIGNAL ;
    PORT
      LAYER Metal3 ;
        RECT  2274.6 181.66 2275 182.06 ;
    END
  END exec_req_i.address[4]
  PIN exec_req_i.address[5]
    DIRECTION INPUT ;
    USE SIGNAL ;
    PORT
      LAYER Metal3 ;
        RECT  2274.6 183.34 2275 183.74 ;
    END
  END exec_req_i.address[5]
  PIN exec_req_i.address[6]
    DIRECTION INPUT ;
    USE SIGNAL ;
    PORT
      LAYER Metal3 ;
        RECT  2274.6 185.02 2275 185.42 ;
    END
  END exec_req_i.address[6]
  PIN exec_req_i.address[7]
    DIRECTION INPUT ;
    USE SIGNAL ;
    PORT
      LAYER Metal3 ;
        RECT  2274.6 186.7 2275 187.1 ;
    END
  END exec_req_i.address[7]
  PIN exec_req_i.address[8]
    DIRECTION INPUT ;
    USE SIGNAL ;
    PORT
      LAYER Metal3 ;
        RECT  2274.6 188.38 2275 188.78 ;
    END
  END exec_req_i.address[8]
  PIN exec_req_i.address[9]
    DIRECTION INPUT ;
    USE SIGNAL ;
    PORT
      LAYER Metal3 ;
        RECT  2274.6 190.06 2275 190.46 ;
    END
  END exec_req_i.address[9]
  PIN exec_req_i.outside
    DIRECTION INPUT ;
    USE SIGNAL ;
    PORT
      LAYER Metal3 ;
        RECT  2274.6 169.9 2275 170.3 ;
    END
  END exec_req_i.outside
  PIN exec_req_i.probe
    DIRECTION INPUT ;
    USE SIGNAL ;
    PORT
      LAYER Metal3 ;
        RECT  2274.6 170.74 2275 171.14 ;
    END
  END exec_req_i.probe
  PIN exec_req_i.size[0]
    DIRECTION INPUT ;
    USE SIGNAL ;
    PORT
      LAYER Metal3 ;
        RECT  2274.6 174.1 2275 174.5 ;
    END
  END exec_req_i.size[0]
  PIN exec_req_i.size[1]
    DIRECTION INPUT ;
    USE SIGNAL ;
    PORT
      LAYER Metal3 ;
        RECT  2274.6 176.62 2275 177.02 ;
    END
  END exec_req_i.size[1]
  PIN exec_req_i.valid
    DIRECTION INPUT ;
    USE SIGNAL ;
    PORT
      LAYER Metal3 ;
        RECT  2274.6 171.58 2275 171.98 ;
    END
  END exec_req_i.valid
  PIN exec_req_i.wdata[0]
    DIRECTION INPUT ;
    USE SIGNAL ;
    PORT
      LAYER Metal3 ;
        RECT  2274.6 174.94 2275 175.34 ;
    END
  END exec_req_i.wdata[0]
  PIN exec_req_i.wdata[10]
    DIRECTION INPUT ;
    USE SIGNAL ;
    PORT
      LAYER Metal3 ;
        RECT  2274.6 192.58 2275 192.98 ;
    END
  END exec_req_i.wdata[10]
  PIN exec_req_i.wdata[11]
    DIRECTION INPUT ;
    USE SIGNAL ;
    PORT
      LAYER Metal3 ;
        RECT  2274.6 194.26 2275 194.66 ;
    END
  END exec_req_i.wdata[11]
  PIN exec_req_i.wdata[12]
    DIRECTION INPUT ;
    USE SIGNAL ;
    PORT
      LAYER Metal3 ;
        RECT  2274.6 195.94 2275 196.34 ;
    END
  END exec_req_i.wdata[12]
  PIN exec_req_i.wdata[13]
    DIRECTION INPUT ;
    USE SIGNAL ;
    PORT
      LAYER Metal3 ;
        RECT  2274.6 197.62 2275 198.02 ;
    END
  END exec_req_i.wdata[13]
  PIN exec_req_i.wdata[14]
    DIRECTION INPUT ;
    USE SIGNAL ;
    PORT
      LAYER Metal3 ;
        RECT  2274.6 199.3 2275 199.7 ;
    END
  END exec_req_i.wdata[14]
  PIN exec_req_i.wdata[15]
    DIRECTION INPUT ;
    USE SIGNAL ;
    PORT
      LAYER Metal3 ;
        RECT  2274.6 200.98 2275 201.38 ;
    END
  END exec_req_i.wdata[15]
  PIN exec_req_i.wdata[16]
    DIRECTION INPUT ;
    USE SIGNAL ;
    PORT
      LAYER Metal3 ;
        RECT  2274.6 202.66 2275 203.06 ;
    END
  END exec_req_i.wdata[16]
  PIN exec_req_i.wdata[17]
    DIRECTION INPUT ;
    USE SIGNAL ;
    PORT
      LAYER Metal3 ;
        RECT  2274.6 204.34 2275 204.74 ;
    END
  END exec_req_i.wdata[17]
  PIN exec_req_i.wdata[18]
    DIRECTION INPUT ;
    USE SIGNAL ;
    PORT
      LAYER Metal3 ;
        RECT  2274.6 206.02 2275 206.42 ;
    END
  END exec_req_i.wdata[18]
  PIN exec_req_i.wdata[19]
    DIRECTION INPUT ;
    USE SIGNAL ;
    PORT
      LAYER Metal3 ;
        RECT  2274.6 207.7 2275 208.1 ;
    END
  END exec_req_i.wdata[19]
  PIN exec_req_i.wdata[1]
    DIRECTION INPUT ;
    USE SIGNAL ;
    PORT
      LAYER Metal3 ;
        RECT  2274.6 177.46 2275 177.86 ;
    END
  END exec_req_i.wdata[1]
  PIN exec_req_i.wdata[20]
    DIRECTION INPUT ;
    USE SIGNAL ;
    PORT
      LAYER Metal3 ;
        RECT  2274.6 209.38 2275 209.78 ;
    END
  END exec_req_i.wdata[20]
  PIN exec_req_i.wdata[21]
    DIRECTION INPUT ;
    USE SIGNAL ;
    PORT
      LAYER Metal3 ;
        RECT  2274.6 211.06 2275 211.46 ;
    END
  END exec_req_i.wdata[21]
  PIN exec_req_i.wdata[22]
    DIRECTION INPUT ;
    USE SIGNAL ;
    PORT
      LAYER Metal3 ;
        RECT  2274.6 212.74 2275 213.14 ;
    END
  END exec_req_i.wdata[22]
  PIN exec_req_i.wdata[23]
    DIRECTION INPUT ;
    USE SIGNAL ;
    PORT
      LAYER Metal3 ;
        RECT  2274.6 214.42 2275 214.82 ;
    END
  END exec_req_i.wdata[23]
  PIN exec_req_i.wdata[24]
    DIRECTION INPUT ;
    USE SIGNAL ;
    PORT
      LAYER Metal3 ;
        RECT  2274.6 216.1 2275 216.5 ;
    END
  END exec_req_i.wdata[24]
  PIN exec_req_i.wdata[25]
    DIRECTION INPUT ;
    USE SIGNAL ;
    PORT
      LAYER Metal3 ;
        RECT  2274.6 217.78 2275 218.18 ;
    END
  END exec_req_i.wdata[25]
  PIN exec_req_i.wdata[26]
    DIRECTION INPUT ;
    USE SIGNAL ;
    PORT
      LAYER Metal3 ;
        RECT  2274.6 219.46 2275 219.86 ;
    END
  END exec_req_i.wdata[26]
  PIN exec_req_i.wdata[27]
    DIRECTION INPUT ;
    USE SIGNAL ;
    PORT
      LAYER Metal3 ;
        RECT  2274.6 221.14 2275 221.54 ;
    END
  END exec_req_i.wdata[27]
  PIN exec_req_i.wdata[28]
    DIRECTION INPUT ;
    USE SIGNAL ;
    PORT
      LAYER Metal3 ;
        RECT  2274.6 222.82 2275 223.22 ;
    END
  END exec_req_i.wdata[28]
  PIN exec_req_i.wdata[29]
    DIRECTION INPUT ;
    USE SIGNAL ;
    PORT
      LAYER Metal3 ;
        RECT  2274.6 224.5 2275 224.9 ;
    END
  END exec_req_i.wdata[29]
  PIN exec_req_i.wdata[2]
    DIRECTION INPUT ;
    USE SIGNAL ;
    PORT
      LAYER Metal3 ;
        RECT  2274.6 179.14 2275 179.54 ;
    END
  END exec_req_i.wdata[2]
  PIN exec_req_i.wdata[30]
    DIRECTION INPUT ;
    USE SIGNAL ;
    PORT
      LAYER Metal3 ;
        RECT  2274.6 226.18 2275 226.58 ;
    END
  END exec_req_i.wdata[30]
  PIN exec_req_i.wdata[31]
    DIRECTION INPUT ;
    USE SIGNAL ;
    PORT
      LAYER Metal3 ;
        RECT  2274.6 227.86 2275 228.26 ;
    END
  END exec_req_i.wdata[31]
  PIN exec_req_i.wdata[32]
    DIRECTION INPUT ;
    USE SIGNAL ;
    PORT
      LAYER Metal3 ;
        RECT  2274.6 228.7 2275 229.1 ;
    END
  END exec_req_i.wdata[32]
  PIN exec_req_i.wdata[33]
    DIRECTION INPUT ;
    USE SIGNAL ;
    PORT
      LAYER Metal3 ;
        RECT  2274.6 229.54 2275 229.94 ;
    END
  END exec_req_i.wdata[33]
  PIN exec_req_i.wdata[34]
    DIRECTION INPUT ;
    USE SIGNAL ;
    PORT
      LAYER Metal3 ;
        RECT  2274.6 230.38 2275 230.78 ;
    END
  END exec_req_i.wdata[34]
  PIN exec_req_i.wdata[35]
    DIRECTION INPUT ;
    USE SIGNAL ;
    PORT
      LAYER Metal3 ;
        RECT  2274.6 231.22 2275 231.62 ;
    END
  END exec_req_i.wdata[35]
  PIN exec_req_i.wdata[36]
    DIRECTION INPUT ;
    USE SIGNAL ;
    PORT
      LAYER Metal3 ;
        RECT  2274.6 232.06 2275 232.46 ;
    END
  END exec_req_i.wdata[36]
  PIN exec_req_i.wdata[37]
    DIRECTION INPUT ;
    USE SIGNAL ;
    PORT
      LAYER Metal3 ;
        RECT  2274.6 232.9 2275 233.3 ;
    END
  END exec_req_i.wdata[37]
  PIN exec_req_i.wdata[38]
    DIRECTION INPUT ;
    USE SIGNAL ;
    PORT
      LAYER Metal3 ;
        RECT  2274.6 233.74 2275 234.14 ;
    END
  END exec_req_i.wdata[38]
  PIN exec_req_i.wdata[39]
    DIRECTION INPUT ;
    USE SIGNAL ;
    PORT
      LAYER Metal3 ;
        RECT  2274.6 234.58 2275 234.98 ;
    END
  END exec_req_i.wdata[39]
  PIN exec_req_i.wdata[3]
    DIRECTION INPUT ;
    USE SIGNAL ;
    PORT
      LAYER Metal3 ;
        RECT  2274.6 180.82 2275 181.22 ;
    END
  END exec_req_i.wdata[3]
  PIN exec_req_i.wdata[40]
    DIRECTION INPUT ;
    USE SIGNAL ;
    PORT
      LAYER Metal3 ;
        RECT  2274.6 235.42 2275 235.82 ;
    END
  END exec_req_i.wdata[40]
  PIN exec_req_i.wdata[41]
    DIRECTION INPUT ;
    USE SIGNAL ;
    PORT
      LAYER Metal3 ;
        RECT  2274.6 236.26 2275 236.66 ;
    END
  END exec_req_i.wdata[41]
  PIN exec_req_i.wdata[42]
    DIRECTION INPUT ;
    USE SIGNAL ;
    PORT
      LAYER Metal3 ;
        RECT  2274.6 237.1 2275 237.5 ;
    END
  END exec_req_i.wdata[42]
  PIN exec_req_i.wdata[43]
    DIRECTION INPUT ;
    USE SIGNAL ;
    PORT
      LAYER Metal3 ;
        RECT  2274.6 237.94 2275 238.34 ;
    END
  END exec_req_i.wdata[43]
  PIN exec_req_i.wdata[44]
    DIRECTION INPUT ;
    USE SIGNAL ;
    PORT
      LAYER Metal3 ;
        RECT  2274.6 238.78 2275 239.18 ;
    END
  END exec_req_i.wdata[44]
  PIN exec_req_i.wdata[45]
    DIRECTION INPUT ;
    USE SIGNAL ;
    PORT
      LAYER Metal3 ;
        RECT  2274.6 239.62 2275 240.02 ;
    END
  END exec_req_i.wdata[45]
  PIN exec_req_i.wdata[46]
    DIRECTION INPUT ;
    USE SIGNAL ;
    PORT
      LAYER Metal3 ;
        RECT  2274.6 240.46 2275 240.86 ;
    END
  END exec_req_i.wdata[46]
  PIN exec_req_i.wdata[47]
    DIRECTION INPUT ;
    USE SIGNAL ;
    PORT
      LAYER Metal3 ;
        RECT  2274.6 241.3 2275 241.7 ;
    END
  END exec_req_i.wdata[47]
  PIN exec_req_i.wdata[48]
    DIRECTION INPUT ;
    USE SIGNAL ;
    PORT
      LAYER Metal3 ;
        RECT  2274.6 242.14 2275 242.54 ;
    END
  END exec_req_i.wdata[48]
  PIN exec_req_i.wdata[49]
    DIRECTION INPUT ;
    USE SIGNAL ;
    PORT
      LAYER Metal3 ;
        RECT  2274.6 242.98 2275 243.38 ;
    END
  END exec_req_i.wdata[49]
  PIN exec_req_i.wdata[4]
    DIRECTION INPUT ;
    USE SIGNAL ;
    PORT
      LAYER Metal3 ;
        RECT  2274.6 182.5 2275 182.9 ;
    END
  END exec_req_i.wdata[4]
  PIN exec_req_i.wdata[50]
    DIRECTION INPUT ;
    USE SIGNAL ;
    PORT
      LAYER Metal3 ;
        RECT  2274.6 243.82 2275 244.22 ;
    END
  END exec_req_i.wdata[50]
  PIN exec_req_i.wdata[51]
    DIRECTION INPUT ;
    USE SIGNAL ;
    PORT
      LAYER Metal3 ;
        RECT  2274.6 244.66 2275 245.06 ;
    END
  END exec_req_i.wdata[51]
  PIN exec_req_i.wdata[52]
    DIRECTION INPUT ;
    USE SIGNAL ;
    PORT
      LAYER Metal3 ;
        RECT  2274.6 245.5 2275 245.9 ;
    END
  END exec_req_i.wdata[52]
  PIN exec_req_i.wdata[53]
    DIRECTION INPUT ;
    USE SIGNAL ;
    PORT
      LAYER Metal3 ;
        RECT  2274.6 246.34 2275 246.74 ;
    END
  END exec_req_i.wdata[53]
  PIN exec_req_i.wdata[54]
    DIRECTION INPUT ;
    USE SIGNAL ;
    PORT
      LAYER Metal3 ;
        RECT  2274.6 247.18 2275 247.58 ;
    END
  END exec_req_i.wdata[54]
  PIN exec_req_i.wdata[55]
    DIRECTION INPUT ;
    USE SIGNAL ;
    PORT
      LAYER Metal3 ;
        RECT  2274.6 248.02 2275 248.42 ;
    END
  END exec_req_i.wdata[55]
  PIN exec_req_i.wdata[56]
    DIRECTION INPUT ;
    USE SIGNAL ;
    PORT
      LAYER Metal3 ;
        RECT  2274.6 248.86 2275 249.26 ;
    END
  END exec_req_i.wdata[56]
  PIN exec_req_i.wdata[57]
    DIRECTION INPUT ;
    USE SIGNAL ;
    PORT
      LAYER Metal3 ;
        RECT  2274.6 249.7 2275 250.1 ;
    END
  END exec_req_i.wdata[57]
  PIN exec_req_i.wdata[58]
    DIRECTION INPUT ;
    USE SIGNAL ;
    PORT
      LAYER Metal3 ;
        RECT  2274.6 250.54 2275 250.94 ;
    END
  END exec_req_i.wdata[58]
  PIN exec_req_i.wdata[59]
    DIRECTION INPUT ;
    USE SIGNAL ;
    PORT
      LAYER Metal3 ;
        RECT  2274.6 251.38 2275 251.78 ;
    END
  END exec_req_i.wdata[59]
  PIN exec_req_i.wdata[5]
    DIRECTION INPUT ;
    USE SIGNAL ;
    PORT
      LAYER Metal3 ;
        RECT  2274.6 184.18 2275 184.58 ;
    END
  END exec_req_i.wdata[5]
  PIN exec_req_i.wdata[60]
    DIRECTION INPUT ;
    USE SIGNAL ;
    PORT
      LAYER Metal3 ;
        RECT  2274.6 252.22 2275 252.62 ;
    END
  END exec_req_i.wdata[60]
  PIN exec_req_i.wdata[61]
    DIRECTION INPUT ;
    USE SIGNAL ;
    PORT
      LAYER Metal3 ;
        RECT  2274.6 253.06 2275 253.46 ;
    END
  END exec_req_i.wdata[61]
  PIN exec_req_i.wdata[62]
    DIRECTION INPUT ;
    USE SIGNAL ;
    PORT
      LAYER Metal3 ;
        RECT  2274.6 253.9 2275 254.3 ;
    END
  END exec_req_i.wdata[62]
  PIN exec_req_i.wdata[63]
    DIRECTION INPUT ;
    USE SIGNAL ;
    PORT
      LAYER Metal3 ;
        RECT  2274.6 254.74 2275 255.14 ;
    END
  END exec_req_i.wdata[63]
  PIN exec_req_i.wdata[6]
    DIRECTION INPUT ;
    USE SIGNAL ;
    PORT
      LAYER Metal3 ;
        RECT  2274.6 185.86 2275 186.26 ;
    END
  END exec_req_i.wdata[6]
  PIN exec_req_i.wdata[7]
    DIRECTION INPUT ;
    USE SIGNAL ;
    PORT
      LAYER Metal3 ;
        RECT  2274.6 187.54 2275 187.94 ;
    END
  END exec_req_i.wdata[7]
  PIN exec_req_i.wdata[8]
    DIRECTION INPUT ;
    USE SIGNAL ;
    PORT
      LAYER Metal3 ;
        RECT  2274.6 189.22 2275 189.62 ;
    END
  END exec_req_i.wdata[8]
  PIN exec_req_i.wdata[9]
    DIRECTION INPUT ;
    USE SIGNAL ;
    PORT
      LAYER Metal3 ;
        RECT  2274.6 190.9 2275 191.3 ;
    END
  END exec_req_i.wdata[9]
  PIN exec_req_i.write
    DIRECTION INPUT ;
    USE SIGNAL ;
    PORT
      LAYER Metal3 ;
        RECT  2274.6 172.42 2275 172.82 ;
    END
  END exec_req_i.write
  PIN exec_rsp_o.fault
    DIRECTION OUTPUT ;
    USE SIGNAL ;
    PORT
      LAYER Metal3 ;
        RECT  2274.6 276.58 2275 276.98 ;
    END
  END exec_rsp_o.fault
  PIN exec_rsp_o.rdata[0]
    DIRECTION OUTPUT ;
    USE SIGNAL ;
    PORT
      LAYER Metal3 ;
        RECT  2274.6 278.26 2275 278.66 ;
    END
  END exec_rsp_o.rdata[0]
  PIN exec_rsp_o.rdata[10]
    DIRECTION OUTPUT ;
    USE SIGNAL ;
    PORT
      LAYER Metal3 ;
        RECT  2274.6 286.66 2275 287.06 ;
    END
  END exec_rsp_o.rdata[10]
  PIN exec_rsp_o.rdata[11]
    DIRECTION OUTPUT ;
    USE SIGNAL ;
    PORT
      LAYER Metal3 ;
        RECT  2274.6 287.5 2275 287.9 ;
    END
  END exec_rsp_o.rdata[11]
  PIN exec_rsp_o.rdata[12]
    DIRECTION OUTPUT ;
    USE SIGNAL ;
    PORT
      LAYER Metal3 ;
        RECT  2274.6 288.34 2275 288.74 ;
    END
  END exec_rsp_o.rdata[12]
  PIN exec_rsp_o.rdata[13]
    DIRECTION OUTPUT ;
    USE SIGNAL ;
    PORT
      LAYER Metal3 ;
        RECT  2274.6 289.18 2275 289.58 ;
    END
  END exec_rsp_o.rdata[13]
  PIN exec_rsp_o.rdata[14]
    DIRECTION OUTPUT ;
    USE SIGNAL ;
    PORT
      LAYER Metal3 ;
        RECT  2274.6 290.02 2275 290.42 ;
    END
  END exec_rsp_o.rdata[14]
  PIN exec_rsp_o.rdata[15]
    DIRECTION OUTPUT ;
    USE SIGNAL ;
    PORT
      LAYER Metal3 ;
        RECT  2274.6 290.86 2275 291.26 ;
    END
  END exec_rsp_o.rdata[15]
  PIN exec_rsp_o.rdata[16]
    DIRECTION OUTPUT ;
    USE SIGNAL ;
    PORT
      LAYER Metal3 ;
        RECT  2274.6 291.7 2275 292.1 ;
    END
  END exec_rsp_o.rdata[16]
  PIN exec_rsp_o.rdata[17]
    DIRECTION OUTPUT ;
    USE SIGNAL ;
    PORT
      LAYER Metal3 ;
        RECT  2274.6 292.54 2275 292.94 ;
    END
  END exec_rsp_o.rdata[17]
  PIN exec_rsp_o.rdata[18]
    DIRECTION OUTPUT ;
    USE SIGNAL ;
    PORT
      LAYER Metal3 ;
        RECT  2274.6 293.38 2275 293.78 ;
    END
  END exec_rsp_o.rdata[18]
  PIN exec_rsp_o.rdata[19]
    DIRECTION OUTPUT ;
    USE SIGNAL ;
    PORT
      LAYER Metal3 ;
        RECT  2274.6 294.22 2275 294.62 ;
    END
  END exec_rsp_o.rdata[19]
  PIN exec_rsp_o.rdata[1]
    DIRECTION OUTPUT ;
    USE SIGNAL ;
    PORT
      LAYER Metal3 ;
        RECT  2274.6 279.1 2275 279.5 ;
    END
  END exec_rsp_o.rdata[1]
  PIN exec_rsp_o.rdata[20]
    DIRECTION OUTPUT ;
    USE SIGNAL ;
    PORT
      LAYER Metal3 ;
        RECT  2274.6 295.06 2275 295.46 ;
    END
  END exec_rsp_o.rdata[20]
  PIN exec_rsp_o.rdata[21]
    DIRECTION OUTPUT ;
    USE SIGNAL ;
    PORT
      LAYER Metal3 ;
        RECT  2274.6 295.9 2275 296.3 ;
    END
  END exec_rsp_o.rdata[21]
  PIN exec_rsp_o.rdata[22]
    DIRECTION OUTPUT ;
    USE SIGNAL ;
    PORT
      LAYER Metal3 ;
        RECT  2274.6 296.74 2275 297.14 ;
    END
  END exec_rsp_o.rdata[22]
  PIN exec_rsp_o.rdata[23]
    DIRECTION OUTPUT ;
    USE SIGNAL ;
    PORT
      LAYER Metal3 ;
        RECT  2274.6 297.58 2275 297.98 ;
    END
  END exec_rsp_o.rdata[23]
  PIN exec_rsp_o.rdata[24]
    DIRECTION OUTPUT ;
    USE SIGNAL ;
    PORT
      LAYER Metal3 ;
        RECT  2274.6 298.42 2275 298.82 ;
    END
  END exec_rsp_o.rdata[24]
  PIN exec_rsp_o.rdata[25]
    DIRECTION OUTPUT ;
    USE SIGNAL ;
    PORT
      LAYER Metal3 ;
        RECT  2274.6 299.26 2275 299.66 ;
    END
  END exec_rsp_o.rdata[25]
  PIN exec_rsp_o.rdata[26]
    DIRECTION OUTPUT ;
    USE SIGNAL ;
    PORT
      LAYER Metal3 ;
        RECT  2274.6 300.1 2275 300.5 ;
    END
  END exec_rsp_o.rdata[26]
  PIN exec_rsp_o.rdata[27]
    DIRECTION OUTPUT ;
    USE SIGNAL ;
    PORT
      LAYER Metal3 ;
        RECT  2274.6 300.94 2275 301.34 ;
    END
  END exec_rsp_o.rdata[27]
  PIN exec_rsp_o.rdata[28]
    DIRECTION OUTPUT ;
    USE SIGNAL ;
    PORT
      LAYER Metal3 ;
        RECT  2274.6 301.78 2275 302.18 ;
    END
  END exec_rsp_o.rdata[28]
  PIN exec_rsp_o.rdata[29]
    DIRECTION OUTPUT ;
    USE SIGNAL ;
    PORT
      LAYER Metal3 ;
        RECT  2274.6 302.62 2275 303.02 ;
    END
  END exec_rsp_o.rdata[29]
  PIN exec_rsp_o.rdata[2]
    DIRECTION OUTPUT ;
    USE SIGNAL ;
    PORT
      LAYER Metal3 ;
        RECT  2274.6 279.94 2275 280.34 ;
    END
  END exec_rsp_o.rdata[2]
  PIN exec_rsp_o.rdata[30]
    DIRECTION OUTPUT ;
    USE SIGNAL ;
    PORT
      LAYER Metal3 ;
        RECT  2274.6 303.46 2275 303.86 ;
    END
  END exec_rsp_o.rdata[30]
  PIN exec_rsp_o.rdata[31]
    DIRECTION OUTPUT ;
    USE SIGNAL ;
    PORT
      LAYER Metal3 ;
        RECT  2274.6 304.3 2275 304.7 ;
    END
  END exec_rsp_o.rdata[31]
  PIN exec_rsp_o.rdata[32]
    DIRECTION OUTPUT ;
    USE SIGNAL ;
    PORT
      LAYER Metal3 ;
        RECT  2274.6 305.14 2275 305.54 ;
    END
  END exec_rsp_o.rdata[32]
  PIN exec_rsp_o.rdata[33]
    DIRECTION OUTPUT ;
    USE SIGNAL ;
    PORT
      LAYER Metal3 ;
        RECT  2274.6 305.98 2275 306.38 ;
    END
  END exec_rsp_o.rdata[33]
  PIN exec_rsp_o.rdata[34]
    DIRECTION OUTPUT ;
    USE SIGNAL ;
    PORT
      LAYER Metal3 ;
        RECT  2274.6 306.82 2275 307.22 ;
    END
  END exec_rsp_o.rdata[34]
  PIN exec_rsp_o.rdata[35]
    DIRECTION OUTPUT ;
    USE SIGNAL ;
    PORT
      LAYER Metal3 ;
        RECT  2274.6 307.66 2275 308.06 ;
    END
  END exec_rsp_o.rdata[35]
  PIN exec_rsp_o.rdata[36]
    DIRECTION OUTPUT ;
    USE SIGNAL ;
    PORT
      LAYER Metal3 ;
        RECT  2274.6 308.5 2275 308.9 ;
    END
  END exec_rsp_o.rdata[36]
  PIN exec_rsp_o.rdata[37]
    DIRECTION OUTPUT ;
    USE SIGNAL ;
    PORT
      LAYER Metal3 ;
        RECT  2274.6 309.34 2275 309.74 ;
    END
  END exec_rsp_o.rdata[37]
  PIN exec_rsp_o.rdata[38]
    DIRECTION OUTPUT ;
    USE SIGNAL ;
    PORT
      LAYER Metal3 ;
        RECT  2274.6 310.18 2275 310.58 ;
    END
  END exec_rsp_o.rdata[38]
  PIN exec_rsp_o.rdata[39]
    DIRECTION OUTPUT ;
    USE SIGNAL ;
    PORT
      LAYER Metal3 ;
        RECT  2274.6 311.02 2275 311.42 ;
    END
  END exec_rsp_o.rdata[39]
  PIN exec_rsp_o.rdata[3]
    DIRECTION OUTPUT ;
    USE SIGNAL ;
    PORT
      LAYER Metal3 ;
        RECT  2274.6 280.78 2275 281.18 ;
    END
  END exec_rsp_o.rdata[3]
  PIN exec_rsp_o.rdata[40]
    DIRECTION OUTPUT ;
    USE SIGNAL ;
    PORT
      LAYER Metal3 ;
        RECT  2274.6 311.86 2275 312.26 ;
    END
  END exec_rsp_o.rdata[40]
  PIN exec_rsp_o.rdata[41]
    DIRECTION OUTPUT ;
    USE SIGNAL ;
    PORT
      LAYER Metal3 ;
        RECT  2274.6 312.7 2275 313.1 ;
    END
  END exec_rsp_o.rdata[41]
  PIN exec_rsp_o.rdata[42]
    DIRECTION OUTPUT ;
    USE SIGNAL ;
    PORT
      LAYER Metal3 ;
        RECT  2274.6 313.54 2275 313.94 ;
    END
  END exec_rsp_o.rdata[42]
  PIN exec_rsp_o.rdata[43]
    DIRECTION OUTPUT ;
    USE SIGNAL ;
    PORT
      LAYER Metal3 ;
        RECT  2274.6 314.38 2275 314.78 ;
    END
  END exec_rsp_o.rdata[43]
  PIN exec_rsp_o.rdata[44]
    DIRECTION OUTPUT ;
    USE SIGNAL ;
    PORT
      LAYER Metal3 ;
        RECT  2274.6 315.22 2275 315.62 ;
    END
  END exec_rsp_o.rdata[44]
  PIN exec_rsp_o.rdata[45]
    DIRECTION OUTPUT ;
    USE SIGNAL ;
    PORT
      LAYER Metal3 ;
        RECT  2274.6 316.06 2275 316.46 ;
    END
  END exec_rsp_o.rdata[45]
  PIN exec_rsp_o.rdata[46]
    DIRECTION OUTPUT ;
    USE SIGNAL ;
    PORT
      LAYER Metal3 ;
        RECT  2274.6 316.9 2275 317.3 ;
    END
  END exec_rsp_o.rdata[46]
  PIN exec_rsp_o.rdata[47]
    DIRECTION OUTPUT ;
    USE SIGNAL ;
    PORT
      LAYER Metal3 ;
        RECT  2274.6 317.74 2275 318.14 ;
    END
  END exec_rsp_o.rdata[47]
  PIN exec_rsp_o.rdata[48]
    DIRECTION OUTPUT ;
    USE SIGNAL ;
    PORT
      LAYER Metal3 ;
        RECT  2274.6 318.58 2275 318.98 ;
    END
  END exec_rsp_o.rdata[48]
  PIN exec_rsp_o.rdata[49]
    DIRECTION OUTPUT ;
    USE SIGNAL ;
    PORT
      LAYER Metal3 ;
        RECT  2274.6 319.42 2275 319.82 ;
    END
  END exec_rsp_o.rdata[49]
  PIN exec_rsp_o.rdata[4]
    DIRECTION OUTPUT ;
    USE SIGNAL ;
    PORT
      LAYER Metal3 ;
        RECT  2274.6 281.62 2275 282.02 ;
    END
  END exec_rsp_o.rdata[4]
  PIN exec_rsp_o.rdata[50]
    DIRECTION OUTPUT ;
    USE SIGNAL ;
    PORT
      LAYER Metal3 ;
        RECT  2274.6 320.26 2275 320.66 ;
    END
  END exec_rsp_o.rdata[50]
  PIN exec_rsp_o.rdata[51]
    DIRECTION OUTPUT ;
    USE SIGNAL ;
    PORT
      LAYER Metal3 ;
        RECT  2274.6 321.1 2275 321.5 ;
    END
  END exec_rsp_o.rdata[51]
  PIN exec_rsp_o.rdata[52]
    DIRECTION OUTPUT ;
    USE SIGNAL ;
    PORT
      LAYER Metal3 ;
        RECT  2274.6 321.94 2275 322.34 ;
    END
  END exec_rsp_o.rdata[52]
  PIN exec_rsp_o.rdata[53]
    DIRECTION OUTPUT ;
    USE SIGNAL ;
    PORT
      LAYER Metal3 ;
        RECT  2274.6 322.78 2275 323.18 ;
    END
  END exec_rsp_o.rdata[53]
  PIN exec_rsp_o.rdata[54]
    DIRECTION OUTPUT ;
    USE SIGNAL ;
    PORT
      LAYER Metal3 ;
        RECT  2274.6 323.62 2275 324.02 ;
    END
  END exec_rsp_o.rdata[54]
  PIN exec_rsp_o.rdata[55]
    DIRECTION OUTPUT ;
    USE SIGNAL ;
    PORT
      LAYER Metal3 ;
        RECT  2274.6 324.46 2275 324.86 ;
    END
  END exec_rsp_o.rdata[55]
  PIN exec_rsp_o.rdata[56]
    DIRECTION OUTPUT ;
    USE SIGNAL ;
    PORT
      LAYER Metal3 ;
        RECT  2274.6 325.3 2275 325.7 ;
    END
  END exec_rsp_o.rdata[56]
  PIN exec_rsp_o.rdata[57]
    DIRECTION OUTPUT ;
    USE SIGNAL ;
    PORT
      LAYER Metal3 ;
        RECT  2274.6 326.14 2275 326.54 ;
    END
  END exec_rsp_o.rdata[57]
  PIN exec_rsp_o.rdata[58]
    DIRECTION OUTPUT ;
    USE SIGNAL ;
    PORT
      LAYER Metal3 ;
        RECT  2274.6 326.98 2275 327.38 ;
    END
  END exec_rsp_o.rdata[58]
  PIN exec_rsp_o.rdata[59]
    DIRECTION OUTPUT ;
    USE SIGNAL ;
    PORT
      LAYER Metal3 ;
        RECT  2274.6 327.82 2275 328.22 ;
    END
  END exec_rsp_o.rdata[59]
  PIN exec_rsp_o.rdata[5]
    DIRECTION OUTPUT ;
    USE SIGNAL ;
    PORT
      LAYER Metal3 ;
        RECT  2274.6 282.46 2275 282.86 ;
    END
  END exec_rsp_o.rdata[5]
  PIN exec_rsp_o.rdata[60]
    DIRECTION OUTPUT ;
    USE SIGNAL ;
    PORT
      LAYER Metal3 ;
        RECT  2274.6 328.66 2275 329.06 ;
    END
  END exec_rsp_o.rdata[60]
  PIN exec_rsp_o.rdata[61]
    DIRECTION OUTPUT ;
    USE SIGNAL ;
    PORT
      LAYER Metal3 ;
        RECT  2274.6 329.5 2275 329.9 ;
    END
  END exec_rsp_o.rdata[61]
  PIN exec_rsp_o.rdata[62]
    DIRECTION OUTPUT ;
    USE SIGNAL ;
    PORT
      LAYER Metal3 ;
        RECT  2274.6 330.34 2275 330.74 ;
    END
  END exec_rsp_o.rdata[62]
  PIN exec_rsp_o.rdata[63]
    DIRECTION OUTPUT ;
    USE SIGNAL ;
    PORT
      LAYER Metal3 ;
        RECT  2274.6 331.18 2275 331.58 ;
    END
  END exec_rsp_o.rdata[63]
  PIN exec_rsp_o.rdata[6]
    DIRECTION OUTPUT ;
    USE SIGNAL ;
    PORT
      LAYER Metal3 ;
        RECT  2274.6 283.3 2275 283.7 ;
    END
  END exec_rsp_o.rdata[6]
  PIN exec_rsp_o.rdata[7]
    DIRECTION OUTPUT ;
    USE SIGNAL ;
    PORT
      LAYER Metal3 ;
        RECT  2274.6 284.14 2275 284.54 ;
    END
  END exec_rsp_o.rdata[7]
  PIN exec_rsp_o.rdata[8]
    DIRECTION OUTPUT ;
    USE SIGNAL ;
    PORT
      LAYER Metal3 ;
        RECT  2274.6 284.98 2275 285.38 ;
    END
  END exec_rsp_o.rdata[8]
  PIN exec_rsp_o.rdata[9]
    DIRECTION OUTPUT ;
    USE SIGNAL ;
    PORT
      LAYER Metal3 ;
        RECT  2274.6 285.82 2275 286.22 ;
    END
  END exec_rsp_o.rdata[9]
  PIN exec_rsp_o.valid
    DIRECTION OUTPUT ;
    USE SIGNAL ;
    PORT
      LAYER Metal3 ;
        RECT  2274.6 277.42 2275 277.82 ;
    END
  END exec_rsp_o.valid
  PIN reset_i
    DIRECTION INPUT ;
    USE SIGNAL ;
    PORT
      LAYER Metal3 ;
        RECT  2274.6 944.38 2275 944.78 ;
    END
  END reset_i
  PIN stack_ready_o
    DIRECTION OUTPUT ;
    USE SIGNAL ;
    PORT
      LAYER Metal3 ;
        RECT  2274.6 827.62 2275 828.02 ;
    END
  END stack_ready_o
  PIN stack_req_i.address[0]
    DIRECTION INPUT ;
    USE SIGNAL ;
    PORT
      LAYER Metal3 ;
        RECT  2274.6 735.22 2275 735.62 ;
    END
  END stack_req_i.address[0]
  PIN stack_req_i.address[10]
    DIRECTION INPUT ;
    USE SIGNAL ;
    PORT
      LAYER Metal3 ;
        RECT  2274.6 753.7 2275 754.1 ;
    END
  END stack_req_i.address[10]
  PIN stack_req_i.address[11]
    DIRECTION INPUT ;
    USE SIGNAL ;
    PORT
      LAYER Metal3 ;
        RECT  2274.6 755.38 2275 755.78 ;
    END
  END stack_req_i.address[11]
  PIN stack_req_i.address[12]
    DIRECTION INPUT ;
    USE SIGNAL ;
    PORT
      LAYER Metal3 ;
        RECT  2274.6 757.06 2275 757.46 ;
    END
  END stack_req_i.address[12]
  PIN stack_req_i.address[13]
    DIRECTION INPUT ;
    USE SIGNAL ;
    PORT
      LAYER Metal3 ;
        RECT  2274.6 758.74 2275 759.14 ;
    END
  END stack_req_i.address[13]
  PIN stack_req_i.address[14]
    DIRECTION INPUT ;
    USE SIGNAL ;
    PORT
      LAYER Metal3 ;
        RECT  2274.6 760.42 2275 760.82 ;
    END
  END stack_req_i.address[14]
  PIN stack_req_i.address[15]
    DIRECTION INPUT ;
    USE SIGNAL ;
    PORT
      LAYER Metal3 ;
        RECT  2274.6 762.1 2275 762.5 ;
    END
  END stack_req_i.address[15]
  PIN stack_req_i.address[16]
    DIRECTION INPUT ;
    USE SIGNAL ;
    PORT
      LAYER Metal3 ;
        RECT  2274.6 763.78 2275 764.18 ;
    END
  END stack_req_i.address[16]
  PIN stack_req_i.address[17]
    DIRECTION INPUT ;
    USE SIGNAL ;
    PORT
      LAYER Metal3 ;
        RECT  2274.6 765.46 2275 765.86 ;
    END
  END stack_req_i.address[17]
  PIN stack_req_i.address[18]
    DIRECTION INPUT ;
    USE SIGNAL ;
    PORT
      LAYER Metal3 ;
        RECT  2274.6 767.14 2275 767.54 ;
    END
  END stack_req_i.address[18]
  PIN stack_req_i.address[19]
    DIRECTION INPUT ;
    USE SIGNAL ;
    PORT
      LAYER Metal3 ;
        RECT  2274.6 768.82 2275 769.22 ;
    END
  END stack_req_i.address[19]
  PIN stack_req_i.address[1]
    DIRECTION INPUT ;
    USE SIGNAL ;
    PORT
      LAYER Metal3 ;
        RECT  2274.6 737.74 2275 738.14 ;
    END
  END stack_req_i.address[1]
  PIN stack_req_i.address[20]
    DIRECTION INPUT ;
    USE SIGNAL ;
    PORT
      LAYER Metal3 ;
        RECT  2274.6 770.5 2275 770.9 ;
    END
  END stack_req_i.address[20]
  PIN stack_req_i.address[21]
    DIRECTION INPUT ;
    USE SIGNAL ;
    PORT
      LAYER Metal3 ;
        RECT  2274.6 772.18 2275 772.58 ;
    END
  END stack_req_i.address[21]
  PIN stack_req_i.address[22]
    DIRECTION INPUT ;
    USE SIGNAL ;
    PORT
      LAYER Metal3 ;
        RECT  2274.6 773.86 2275 774.26 ;
    END
  END stack_req_i.address[22]
  PIN stack_req_i.address[23]
    DIRECTION INPUT ;
    USE SIGNAL ;
    PORT
      LAYER Metal3 ;
        RECT  2274.6 775.54 2275 775.94 ;
    END
  END stack_req_i.address[23]
  PIN stack_req_i.address[24]
    DIRECTION INPUT ;
    USE SIGNAL ;
    PORT
      LAYER Metal3 ;
        RECT  2274.6 777.22 2275 777.62 ;
    END
  END stack_req_i.address[24]
  PIN stack_req_i.address[25]
    DIRECTION INPUT ;
    USE SIGNAL ;
    PORT
      LAYER Metal3 ;
        RECT  2274.6 778.9 2275 779.3 ;
    END
  END stack_req_i.address[25]
  PIN stack_req_i.address[26]
    DIRECTION INPUT ;
    USE SIGNAL ;
    PORT
      LAYER Metal3 ;
        RECT  2274.6 780.58 2275 780.98 ;
    END
  END stack_req_i.address[26]
  PIN stack_req_i.address[27]
    DIRECTION INPUT ;
    USE SIGNAL ;
    PORT
      LAYER Metal3 ;
        RECT  2274.6 782.26 2275 782.66 ;
    END
  END stack_req_i.address[27]
  PIN stack_req_i.address[28]
    DIRECTION INPUT ;
    USE SIGNAL ;
    PORT
      LAYER Metal3 ;
        RECT  2274.6 783.94 2275 784.34 ;
    END
  END stack_req_i.address[28]
  PIN stack_req_i.address[29]
    DIRECTION INPUT ;
    USE SIGNAL ;
    PORT
      LAYER Metal3 ;
        RECT  2274.6 785.62 2275 786.02 ;
    END
  END stack_req_i.address[29]
  PIN stack_req_i.address[2]
    DIRECTION INPUT ;
    USE SIGNAL ;
    PORT
      LAYER Metal3 ;
        RECT  2274.6 740.26 2275 740.66 ;
    END
  END stack_req_i.address[2]
  PIN stack_req_i.address[30]
    DIRECTION INPUT ;
    USE SIGNAL ;
    PORT
      LAYER Metal3 ;
        RECT  2274.6 787.3 2275 787.7 ;
    END
  END stack_req_i.address[30]
  PIN stack_req_i.address[31]
    DIRECTION INPUT ;
    USE SIGNAL ;
    PORT
      LAYER Metal3 ;
        RECT  2274.6 788.98 2275 789.38 ;
    END
  END stack_req_i.address[31]
  PIN stack_req_i.address[3]
    DIRECTION INPUT ;
    USE SIGNAL ;
    PORT
      LAYER Metal3 ;
        RECT  2274.6 741.94 2275 742.34 ;
    END
  END stack_req_i.address[3]
  PIN stack_req_i.address[4]
    DIRECTION INPUT ;
    USE SIGNAL ;
    PORT
      LAYER Metal3 ;
        RECT  2274.6 743.62 2275 744.02 ;
    END
  END stack_req_i.address[4]
  PIN stack_req_i.address[5]
    DIRECTION INPUT ;
    USE SIGNAL ;
    PORT
      LAYER Metal3 ;
        RECT  2274.6 745.3 2275 745.7 ;
    END
  END stack_req_i.address[5]
  PIN stack_req_i.address[6]
    DIRECTION INPUT ;
    USE SIGNAL ;
    PORT
      LAYER Metal3 ;
        RECT  2274.6 746.98 2275 747.38 ;
    END
  END stack_req_i.address[6]
  PIN stack_req_i.address[7]
    DIRECTION INPUT ;
    USE SIGNAL ;
    PORT
      LAYER Metal3 ;
        RECT  2274.6 748.66 2275 749.06 ;
    END
  END stack_req_i.address[7]
  PIN stack_req_i.address[8]
    DIRECTION INPUT ;
    USE SIGNAL ;
    PORT
      LAYER Metal3 ;
        RECT  2274.6 750.34 2275 750.74 ;
    END
  END stack_req_i.address[8]
  PIN stack_req_i.address[9]
    DIRECTION INPUT ;
    USE SIGNAL ;
    PORT
      LAYER Metal3 ;
        RECT  2274.6 752.02 2275 752.42 ;
    END
  END stack_req_i.address[9]
  PIN stack_req_i.probe
    DIRECTION INPUT ;
    USE SIGNAL ;
    PORT
      LAYER Metal3 ;
        RECT  2274.6 732.7 2275 733.1 ;
    END
  END stack_req_i.probe
  PIN stack_req_i.size[0]
    DIRECTION INPUT ;
    USE SIGNAL ;
    PORT
      LAYER Metal3 ;
        RECT  2274.6 736.06 2275 736.46 ;
    END
  END stack_req_i.size[0]
  PIN stack_req_i.size[1]
    DIRECTION INPUT ;
    USE SIGNAL ;
    PORT
      LAYER Metal3 ;
        RECT  2274.6 738.58 2275 738.98 ;
    END
  END stack_req_i.size[1]
  PIN stack_req_i.valid
    DIRECTION INPUT ;
    USE SIGNAL ;
    PORT
      LAYER Metal3 ;
        RECT  2274.6 733.54 2275 733.94 ;
    END
  END stack_req_i.valid
  PIN stack_req_i.wdata[0]
    DIRECTION INPUT ;
    USE SIGNAL ;
    PORT
      LAYER Metal3 ;
        RECT  2274.6 736.9 2275 737.3 ;
    END
  END stack_req_i.wdata[0]
  PIN stack_req_i.wdata[10]
    DIRECTION INPUT ;
    USE SIGNAL ;
    PORT
      LAYER Metal3 ;
        RECT  2274.6 754.54 2275 754.94 ;
    END
  END stack_req_i.wdata[10]
  PIN stack_req_i.wdata[11]
    DIRECTION INPUT ;
    USE SIGNAL ;
    PORT
      LAYER Metal3 ;
        RECT  2274.6 756.22 2275 756.62 ;
    END
  END stack_req_i.wdata[11]
  PIN stack_req_i.wdata[12]
    DIRECTION INPUT ;
    USE SIGNAL ;
    PORT
      LAYER Metal3 ;
        RECT  2274.6 757.9 2275 758.3 ;
    END
  END stack_req_i.wdata[12]
  PIN stack_req_i.wdata[13]
    DIRECTION INPUT ;
    USE SIGNAL ;
    PORT
      LAYER Metal3 ;
        RECT  2274.6 759.58 2275 759.98 ;
    END
  END stack_req_i.wdata[13]
  PIN stack_req_i.wdata[14]
    DIRECTION INPUT ;
    USE SIGNAL ;
    PORT
      LAYER Metal3 ;
        RECT  2274.6 761.26 2275 761.66 ;
    END
  END stack_req_i.wdata[14]
  PIN stack_req_i.wdata[15]
    DIRECTION INPUT ;
    USE SIGNAL ;
    PORT
      LAYER Metal3 ;
        RECT  2274.6 762.94 2275 763.34 ;
    END
  END stack_req_i.wdata[15]
  PIN stack_req_i.wdata[16]
    DIRECTION INPUT ;
    USE SIGNAL ;
    PORT
      LAYER Metal3 ;
        RECT  2274.6 764.62 2275 765.02 ;
    END
  END stack_req_i.wdata[16]
  PIN stack_req_i.wdata[17]
    DIRECTION INPUT ;
    USE SIGNAL ;
    PORT
      LAYER Metal3 ;
        RECT  2274.6 766.3 2275 766.7 ;
    END
  END stack_req_i.wdata[17]
  PIN stack_req_i.wdata[18]
    DIRECTION INPUT ;
    USE SIGNAL ;
    PORT
      LAYER Metal3 ;
        RECT  2274.6 767.98 2275 768.38 ;
    END
  END stack_req_i.wdata[18]
  PIN stack_req_i.wdata[19]
    DIRECTION INPUT ;
    USE SIGNAL ;
    PORT
      LAYER Metal3 ;
        RECT  2274.6 769.66 2275 770.06 ;
    END
  END stack_req_i.wdata[19]
  PIN stack_req_i.wdata[1]
    DIRECTION INPUT ;
    USE SIGNAL ;
    PORT
      LAYER Metal3 ;
        RECT  2274.6 739.42 2275 739.82 ;
    END
  END stack_req_i.wdata[1]
  PIN stack_req_i.wdata[20]
    DIRECTION INPUT ;
    USE SIGNAL ;
    PORT
      LAYER Metal3 ;
        RECT  2274.6 771.34 2275 771.74 ;
    END
  END stack_req_i.wdata[20]
  PIN stack_req_i.wdata[21]
    DIRECTION INPUT ;
    USE SIGNAL ;
    PORT
      LAYER Metal3 ;
        RECT  2274.6 773.02 2275 773.42 ;
    END
  END stack_req_i.wdata[21]
  PIN stack_req_i.wdata[22]
    DIRECTION INPUT ;
    USE SIGNAL ;
    PORT
      LAYER Metal3 ;
        RECT  2274.6 774.7 2275 775.1 ;
    END
  END stack_req_i.wdata[22]
  PIN stack_req_i.wdata[23]
    DIRECTION INPUT ;
    USE SIGNAL ;
    PORT
      LAYER Metal3 ;
        RECT  2274.6 776.38 2275 776.78 ;
    END
  END stack_req_i.wdata[23]
  PIN stack_req_i.wdata[24]
    DIRECTION INPUT ;
    USE SIGNAL ;
    PORT
      LAYER Metal3 ;
        RECT  2274.6 778.06 2275 778.46 ;
    END
  END stack_req_i.wdata[24]
  PIN stack_req_i.wdata[25]
    DIRECTION INPUT ;
    USE SIGNAL ;
    PORT
      LAYER Metal3 ;
        RECT  2274.6 779.74 2275 780.14 ;
    END
  END stack_req_i.wdata[25]
  PIN stack_req_i.wdata[26]
    DIRECTION INPUT ;
    USE SIGNAL ;
    PORT
      LAYER Metal3 ;
        RECT  2274.6 781.42 2275 781.82 ;
    END
  END stack_req_i.wdata[26]
  PIN stack_req_i.wdata[27]
    DIRECTION INPUT ;
    USE SIGNAL ;
    PORT
      LAYER Metal3 ;
        RECT  2274.6 783.1 2275 783.5 ;
    END
  END stack_req_i.wdata[27]
  PIN stack_req_i.wdata[28]
    DIRECTION INPUT ;
    USE SIGNAL ;
    PORT
      LAYER Metal3 ;
        RECT  2274.6 784.78 2275 785.18 ;
    END
  END stack_req_i.wdata[28]
  PIN stack_req_i.wdata[29]
    DIRECTION INPUT ;
    USE SIGNAL ;
    PORT
      LAYER Metal3 ;
        RECT  2274.6 786.46 2275 786.86 ;
    END
  END stack_req_i.wdata[29]
  PIN stack_req_i.wdata[2]
    DIRECTION INPUT ;
    USE SIGNAL ;
    PORT
      LAYER Metal3 ;
        RECT  2274.6 741.1 2275 741.5 ;
    END
  END stack_req_i.wdata[2]
  PIN stack_req_i.wdata[30]
    DIRECTION INPUT ;
    USE SIGNAL ;
    PORT
      LAYER Metal3 ;
        RECT  2274.6 788.14 2275 788.54 ;
    END
  END stack_req_i.wdata[30]
  PIN stack_req_i.wdata[31]
    DIRECTION INPUT ;
    USE SIGNAL ;
    PORT
      LAYER Metal3 ;
        RECT  2274.6 789.82 2275 790.22 ;
    END
  END stack_req_i.wdata[31]
  PIN stack_req_i.wdata[32]
    DIRECTION INPUT ;
    USE SIGNAL ;
    PORT
      LAYER Metal3 ;
        RECT  2274.6 790.66 2275 791.06 ;
    END
  END stack_req_i.wdata[32]
  PIN stack_req_i.wdata[33]
    DIRECTION INPUT ;
    USE SIGNAL ;
    PORT
      LAYER Metal3 ;
        RECT  2274.6 791.5 2275 791.9 ;
    END
  END stack_req_i.wdata[33]
  PIN stack_req_i.wdata[34]
    DIRECTION INPUT ;
    USE SIGNAL ;
    PORT
      LAYER Metal3 ;
        RECT  2274.6 792.34 2275 792.74 ;
    END
  END stack_req_i.wdata[34]
  PIN stack_req_i.wdata[35]
    DIRECTION INPUT ;
    USE SIGNAL ;
    PORT
      LAYER Metal3 ;
        RECT  2274.6 793.18 2275 793.58 ;
    END
  END stack_req_i.wdata[35]
  PIN stack_req_i.wdata[36]
    DIRECTION INPUT ;
    USE SIGNAL ;
    PORT
      LAYER Metal3 ;
        RECT  2274.6 794.02 2275 794.42 ;
    END
  END stack_req_i.wdata[36]
  PIN stack_req_i.wdata[37]
    DIRECTION INPUT ;
    USE SIGNAL ;
    PORT
      LAYER Metal3 ;
        RECT  2274.6 794.86 2275 795.26 ;
    END
  END stack_req_i.wdata[37]
  PIN stack_req_i.wdata[38]
    DIRECTION INPUT ;
    USE SIGNAL ;
    PORT
      LAYER Metal3 ;
        RECT  2274.6 795.7 2275 796.1 ;
    END
  END stack_req_i.wdata[38]
  PIN stack_req_i.wdata[39]
    DIRECTION INPUT ;
    USE SIGNAL ;
    PORT
      LAYER Metal3 ;
        RECT  2274.6 796.54 2275 796.94 ;
    END
  END stack_req_i.wdata[39]
  PIN stack_req_i.wdata[3]
    DIRECTION INPUT ;
    USE SIGNAL ;
    PORT
      LAYER Metal3 ;
        RECT  2274.6 742.78 2275 743.18 ;
    END
  END stack_req_i.wdata[3]
  PIN stack_req_i.wdata[40]
    DIRECTION INPUT ;
    USE SIGNAL ;
    PORT
      LAYER Metal3 ;
        RECT  2274.6 797.38 2275 797.78 ;
    END
  END stack_req_i.wdata[40]
  PIN stack_req_i.wdata[41]
    DIRECTION INPUT ;
    USE SIGNAL ;
    PORT
      LAYER Metal3 ;
        RECT  2274.6 798.22 2275 798.62 ;
    END
  END stack_req_i.wdata[41]
  PIN stack_req_i.wdata[42]
    DIRECTION INPUT ;
    USE SIGNAL ;
    PORT
      LAYER Metal3 ;
        RECT  2274.6 799.06 2275 799.46 ;
    END
  END stack_req_i.wdata[42]
  PIN stack_req_i.wdata[43]
    DIRECTION INPUT ;
    USE SIGNAL ;
    PORT
      LAYER Metal3 ;
        RECT  2274.6 799.9 2275 800.3 ;
    END
  END stack_req_i.wdata[43]
  PIN stack_req_i.wdata[44]
    DIRECTION INPUT ;
    USE SIGNAL ;
    PORT
      LAYER Metal3 ;
        RECT  2274.6 800.74 2275 801.14 ;
    END
  END stack_req_i.wdata[44]
  PIN stack_req_i.wdata[45]
    DIRECTION INPUT ;
    USE SIGNAL ;
    PORT
      LAYER Metal3 ;
        RECT  2274.6 801.58 2275 801.98 ;
    END
  END stack_req_i.wdata[45]
  PIN stack_req_i.wdata[46]
    DIRECTION INPUT ;
    USE SIGNAL ;
    PORT
      LAYER Metal3 ;
        RECT  2274.6 802.42 2275 802.82 ;
    END
  END stack_req_i.wdata[46]
  PIN stack_req_i.wdata[47]
    DIRECTION INPUT ;
    USE SIGNAL ;
    PORT
      LAYER Metal3 ;
        RECT  2274.6 803.26 2275 803.66 ;
    END
  END stack_req_i.wdata[47]
  PIN stack_req_i.wdata[48]
    DIRECTION INPUT ;
    USE SIGNAL ;
    PORT
      LAYER Metal3 ;
        RECT  2274.6 804.1 2275 804.5 ;
    END
  END stack_req_i.wdata[48]
  PIN stack_req_i.wdata[49]
    DIRECTION INPUT ;
    USE SIGNAL ;
    PORT
      LAYER Metal3 ;
        RECT  2274.6 804.94 2275 805.34 ;
    END
  END stack_req_i.wdata[49]
  PIN stack_req_i.wdata[4]
    DIRECTION INPUT ;
    USE SIGNAL ;
    PORT
      LAYER Metal3 ;
        RECT  2274.6 744.46 2275 744.86 ;
    END
  END stack_req_i.wdata[4]
  PIN stack_req_i.wdata[50]
    DIRECTION INPUT ;
    USE SIGNAL ;
    PORT
      LAYER Metal3 ;
        RECT  2274.6 805.78 2275 806.18 ;
    END
  END stack_req_i.wdata[50]
  PIN stack_req_i.wdata[51]
    DIRECTION INPUT ;
    USE SIGNAL ;
    PORT
      LAYER Metal3 ;
        RECT  2274.6 806.62 2275 807.02 ;
    END
  END stack_req_i.wdata[51]
  PIN stack_req_i.wdata[52]
    DIRECTION INPUT ;
    USE SIGNAL ;
    PORT
      LAYER Metal3 ;
        RECT  2274.6 807.46 2275 807.86 ;
    END
  END stack_req_i.wdata[52]
  PIN stack_req_i.wdata[53]
    DIRECTION INPUT ;
    USE SIGNAL ;
    PORT
      LAYER Metal3 ;
        RECT  2274.6 808.3 2275 808.7 ;
    END
  END stack_req_i.wdata[53]
  PIN stack_req_i.wdata[54]
    DIRECTION INPUT ;
    USE SIGNAL ;
    PORT
      LAYER Metal3 ;
        RECT  2274.6 809.14 2275 809.54 ;
    END
  END stack_req_i.wdata[54]
  PIN stack_req_i.wdata[55]
    DIRECTION INPUT ;
    USE SIGNAL ;
    PORT
      LAYER Metal3 ;
        RECT  2274.6 809.98 2275 810.38 ;
    END
  END stack_req_i.wdata[55]
  PIN stack_req_i.wdata[56]
    DIRECTION INPUT ;
    USE SIGNAL ;
    PORT
      LAYER Metal3 ;
        RECT  2274.6 810.82 2275 811.22 ;
    END
  END stack_req_i.wdata[56]
  PIN stack_req_i.wdata[57]
    DIRECTION INPUT ;
    USE SIGNAL ;
    PORT
      LAYER Metal3 ;
        RECT  2274.6 811.66 2275 812.06 ;
    END
  END stack_req_i.wdata[57]
  PIN stack_req_i.wdata[58]
    DIRECTION INPUT ;
    USE SIGNAL ;
    PORT
      LAYER Metal3 ;
        RECT  2274.6 812.5 2275 812.9 ;
    END
  END stack_req_i.wdata[58]
  PIN stack_req_i.wdata[59]
    DIRECTION INPUT ;
    USE SIGNAL ;
    PORT
      LAYER Metal3 ;
        RECT  2274.6 813.34 2275 813.74 ;
    END
  END stack_req_i.wdata[59]
  PIN stack_req_i.wdata[5]
    DIRECTION INPUT ;
    USE SIGNAL ;
    PORT
      LAYER Metal3 ;
        RECT  2274.6 746.14 2275 746.54 ;
    END
  END stack_req_i.wdata[5]
  PIN stack_req_i.wdata[60]
    DIRECTION INPUT ;
    USE SIGNAL ;
    PORT
      LAYER Metal3 ;
        RECT  2274.6 814.18 2275 814.58 ;
    END
  END stack_req_i.wdata[60]
  PIN stack_req_i.wdata[61]
    DIRECTION INPUT ;
    USE SIGNAL ;
    PORT
      LAYER Metal3 ;
        RECT  2274.6 815.02 2275 815.42 ;
    END
  END stack_req_i.wdata[61]
  PIN stack_req_i.wdata[62]
    DIRECTION INPUT ;
    USE SIGNAL ;
    PORT
      LAYER Metal3 ;
        RECT  2274.6 815.86 2275 816.26 ;
    END
  END stack_req_i.wdata[62]
  PIN stack_req_i.wdata[63]
    DIRECTION INPUT ;
    USE SIGNAL ;
    PORT
      LAYER Metal3 ;
        RECT  2274.6 816.7 2275 817.1 ;
    END
  END stack_req_i.wdata[63]
  PIN stack_req_i.wdata[6]
    DIRECTION INPUT ;
    USE SIGNAL ;
    PORT
      LAYER Metal3 ;
        RECT  2274.6 747.82 2275 748.22 ;
    END
  END stack_req_i.wdata[6]
  PIN stack_req_i.wdata[7]
    DIRECTION INPUT ;
    USE SIGNAL ;
    PORT
      LAYER Metal3 ;
        RECT  2274.6 749.5 2275 749.9 ;
    END
  END stack_req_i.wdata[7]
  PIN stack_req_i.wdata[8]
    DIRECTION INPUT ;
    USE SIGNAL ;
    PORT
      LAYER Metal3 ;
        RECT  2274.6 751.18 2275 751.58 ;
    END
  END stack_req_i.wdata[8]
  PIN stack_req_i.wdata[9]
    DIRECTION INPUT ;
    USE SIGNAL ;
    PORT
      LAYER Metal3 ;
        RECT  2274.6 752.86 2275 753.26 ;
    END
  END stack_req_i.wdata[9]
  PIN stack_req_i.write
    DIRECTION INPUT ;
    USE SIGNAL ;
    PORT
      LAYER Metal3 ;
        RECT  2274.6 734.38 2275 734.78 ;
    END
  END stack_req_i.write
  PIN stack_rsp_o.fault
    DIRECTION OUTPUT ;
    USE SIGNAL ;
    PORT
      LAYER Metal3 ;
        RECT  2274.6 838.54 2275 838.94 ;
    END
  END stack_rsp_o.fault
  PIN stack_rsp_o.rdata[0]
    DIRECTION OUTPUT ;
    USE SIGNAL ;
    PORT
      LAYER Metal3 ;
        RECT  2274.6 840.22 2275 840.62 ;
    END
  END stack_rsp_o.rdata[0]
  PIN stack_rsp_o.rdata[10]
    DIRECTION OUTPUT ;
    USE SIGNAL ;
    PORT
      LAYER Metal3 ;
        RECT  2274.6 848.62 2275 849.02 ;
    END
  END stack_rsp_o.rdata[10]
  PIN stack_rsp_o.rdata[11]
    DIRECTION OUTPUT ;
    USE SIGNAL ;
    PORT
      LAYER Metal3 ;
        RECT  2274.6 849.46 2275 849.86 ;
    END
  END stack_rsp_o.rdata[11]
  PIN stack_rsp_o.rdata[12]
    DIRECTION OUTPUT ;
    USE SIGNAL ;
    PORT
      LAYER Metal3 ;
        RECT  2274.6 850.3 2275 850.7 ;
    END
  END stack_rsp_o.rdata[12]
  PIN stack_rsp_o.rdata[13]
    DIRECTION OUTPUT ;
    USE SIGNAL ;
    PORT
      LAYER Metal3 ;
        RECT  2274.6 851.14 2275 851.54 ;
    END
  END stack_rsp_o.rdata[13]
  PIN stack_rsp_o.rdata[14]
    DIRECTION OUTPUT ;
    USE SIGNAL ;
    PORT
      LAYER Metal3 ;
        RECT  2274.6 851.98 2275 852.38 ;
    END
  END stack_rsp_o.rdata[14]
  PIN stack_rsp_o.rdata[15]
    DIRECTION OUTPUT ;
    USE SIGNAL ;
    PORT
      LAYER Metal3 ;
        RECT  2274.6 852.82 2275 853.22 ;
    END
  END stack_rsp_o.rdata[15]
  PIN stack_rsp_o.rdata[16]
    DIRECTION OUTPUT ;
    USE SIGNAL ;
    PORT
      LAYER Metal3 ;
        RECT  2274.6 853.66 2275 854.06 ;
    END
  END stack_rsp_o.rdata[16]
  PIN stack_rsp_o.rdata[17]
    DIRECTION OUTPUT ;
    USE SIGNAL ;
    PORT
      LAYER Metal3 ;
        RECT  2274.6 854.5 2275 854.9 ;
    END
  END stack_rsp_o.rdata[17]
  PIN stack_rsp_o.rdata[18]
    DIRECTION OUTPUT ;
    USE SIGNAL ;
    PORT
      LAYER Metal3 ;
        RECT  2274.6 855.34 2275 855.74 ;
    END
  END stack_rsp_o.rdata[18]
  PIN stack_rsp_o.rdata[19]
    DIRECTION OUTPUT ;
    USE SIGNAL ;
    PORT
      LAYER Metal3 ;
        RECT  2274.6 856.18 2275 856.58 ;
    END
  END stack_rsp_o.rdata[19]
  PIN stack_rsp_o.rdata[1]
    DIRECTION OUTPUT ;
    USE SIGNAL ;
    PORT
      LAYER Metal3 ;
        RECT  2274.6 841.06 2275 841.46 ;
    END
  END stack_rsp_o.rdata[1]
  PIN stack_rsp_o.rdata[20]
    DIRECTION OUTPUT ;
    USE SIGNAL ;
    PORT
      LAYER Metal3 ;
        RECT  2274.6 857.02 2275 857.42 ;
    END
  END stack_rsp_o.rdata[20]
  PIN stack_rsp_o.rdata[21]
    DIRECTION OUTPUT ;
    USE SIGNAL ;
    PORT
      LAYER Metal3 ;
        RECT  2274.6 857.86 2275 858.26 ;
    END
  END stack_rsp_o.rdata[21]
  PIN stack_rsp_o.rdata[22]
    DIRECTION OUTPUT ;
    USE SIGNAL ;
    PORT
      LAYER Metal3 ;
        RECT  2274.6 858.7 2275 859.1 ;
    END
  END stack_rsp_o.rdata[22]
  PIN stack_rsp_o.rdata[23]
    DIRECTION OUTPUT ;
    USE SIGNAL ;
    PORT
      LAYER Metal3 ;
        RECT  2274.6 859.54 2275 859.94 ;
    END
  END stack_rsp_o.rdata[23]
  PIN stack_rsp_o.rdata[24]
    DIRECTION OUTPUT ;
    USE SIGNAL ;
    PORT
      LAYER Metal3 ;
        RECT  2274.6 860.38 2275 860.78 ;
    END
  END stack_rsp_o.rdata[24]
  PIN stack_rsp_o.rdata[25]
    DIRECTION OUTPUT ;
    USE SIGNAL ;
    PORT
      LAYER Metal3 ;
        RECT  2274.6 861.22 2275 861.62 ;
    END
  END stack_rsp_o.rdata[25]
  PIN stack_rsp_o.rdata[26]
    DIRECTION OUTPUT ;
    USE SIGNAL ;
    PORT
      LAYER Metal3 ;
        RECT  2274.6 862.06 2275 862.46 ;
    END
  END stack_rsp_o.rdata[26]
  PIN stack_rsp_o.rdata[27]
    DIRECTION OUTPUT ;
    USE SIGNAL ;
    PORT
      LAYER Metal3 ;
        RECT  2274.6 862.9 2275 863.3 ;
    END
  END stack_rsp_o.rdata[27]
  PIN stack_rsp_o.rdata[28]
    DIRECTION OUTPUT ;
    USE SIGNAL ;
    PORT
      LAYER Metal3 ;
        RECT  2274.6 863.74 2275 864.14 ;
    END
  END stack_rsp_o.rdata[28]
  PIN stack_rsp_o.rdata[29]
    DIRECTION OUTPUT ;
    USE SIGNAL ;
    PORT
      LAYER Metal3 ;
        RECT  2274.6 864.58 2275 864.98 ;
    END
  END stack_rsp_o.rdata[29]
  PIN stack_rsp_o.rdata[2]
    DIRECTION OUTPUT ;
    USE SIGNAL ;
    PORT
      LAYER Metal3 ;
        RECT  2274.6 841.9 2275 842.3 ;
    END
  END stack_rsp_o.rdata[2]
  PIN stack_rsp_o.rdata[30]
    DIRECTION OUTPUT ;
    USE SIGNAL ;
    PORT
      LAYER Metal3 ;
        RECT  2274.6 865.42 2275 865.82 ;
    END
  END stack_rsp_o.rdata[30]
  PIN stack_rsp_o.rdata[31]
    DIRECTION OUTPUT ;
    USE SIGNAL ;
    PORT
      LAYER Metal3 ;
        RECT  2274.6 866.26 2275 866.66 ;
    END
  END stack_rsp_o.rdata[31]
  PIN stack_rsp_o.rdata[32]
    DIRECTION OUTPUT ;
    USE SIGNAL ;
    PORT
      LAYER Metal3 ;
        RECT  2274.6 867.1 2275 867.5 ;
    END
  END stack_rsp_o.rdata[32]
  PIN stack_rsp_o.rdata[33]
    DIRECTION OUTPUT ;
    USE SIGNAL ;
    PORT
      LAYER Metal3 ;
        RECT  2274.6 867.94 2275 868.34 ;
    END
  END stack_rsp_o.rdata[33]
  PIN stack_rsp_o.rdata[34]
    DIRECTION OUTPUT ;
    USE SIGNAL ;
    PORT
      LAYER Metal3 ;
        RECT  2274.6 868.78 2275 869.18 ;
    END
  END stack_rsp_o.rdata[34]
  PIN stack_rsp_o.rdata[35]
    DIRECTION OUTPUT ;
    USE SIGNAL ;
    PORT
      LAYER Metal3 ;
        RECT  2274.6 869.62 2275 870.02 ;
    END
  END stack_rsp_o.rdata[35]
  PIN stack_rsp_o.rdata[36]
    DIRECTION OUTPUT ;
    USE SIGNAL ;
    PORT
      LAYER Metal3 ;
        RECT  2274.6 870.46 2275 870.86 ;
    END
  END stack_rsp_o.rdata[36]
  PIN stack_rsp_o.rdata[37]
    DIRECTION OUTPUT ;
    USE SIGNAL ;
    PORT
      LAYER Metal3 ;
        RECT  2274.6 871.3 2275 871.7 ;
    END
  END stack_rsp_o.rdata[37]
  PIN stack_rsp_o.rdata[38]
    DIRECTION OUTPUT ;
    USE SIGNAL ;
    PORT
      LAYER Metal3 ;
        RECT  2274.6 872.14 2275 872.54 ;
    END
  END stack_rsp_o.rdata[38]
  PIN stack_rsp_o.rdata[39]
    DIRECTION OUTPUT ;
    USE SIGNAL ;
    PORT
      LAYER Metal3 ;
        RECT  2274.6 872.98 2275 873.38 ;
    END
  END stack_rsp_o.rdata[39]
  PIN stack_rsp_o.rdata[3]
    DIRECTION OUTPUT ;
    USE SIGNAL ;
    PORT
      LAYER Metal3 ;
        RECT  2274.6 842.74 2275 843.14 ;
    END
  END stack_rsp_o.rdata[3]
  PIN stack_rsp_o.rdata[40]
    DIRECTION OUTPUT ;
    USE SIGNAL ;
    PORT
      LAYER Metal3 ;
        RECT  2274.6 873.82 2275 874.22 ;
    END
  END stack_rsp_o.rdata[40]
  PIN stack_rsp_o.rdata[41]
    DIRECTION OUTPUT ;
    USE SIGNAL ;
    PORT
      LAYER Metal3 ;
        RECT  2274.6 874.66 2275 875.06 ;
    END
  END stack_rsp_o.rdata[41]
  PIN stack_rsp_o.rdata[42]
    DIRECTION OUTPUT ;
    USE SIGNAL ;
    PORT
      LAYER Metal3 ;
        RECT  2274.6 875.5 2275 875.9 ;
    END
  END stack_rsp_o.rdata[42]
  PIN stack_rsp_o.rdata[43]
    DIRECTION OUTPUT ;
    USE SIGNAL ;
    PORT
      LAYER Metal3 ;
        RECT  2274.6 876.34 2275 876.74 ;
    END
  END stack_rsp_o.rdata[43]
  PIN stack_rsp_o.rdata[44]
    DIRECTION OUTPUT ;
    USE SIGNAL ;
    PORT
      LAYER Metal3 ;
        RECT  2274.6 877.18 2275 877.58 ;
    END
  END stack_rsp_o.rdata[44]
  PIN stack_rsp_o.rdata[45]
    DIRECTION OUTPUT ;
    USE SIGNAL ;
    PORT
      LAYER Metal3 ;
        RECT  2274.6 878.02 2275 878.42 ;
    END
  END stack_rsp_o.rdata[45]
  PIN stack_rsp_o.rdata[46]
    DIRECTION OUTPUT ;
    USE SIGNAL ;
    PORT
      LAYER Metal3 ;
        RECT  2274.6 878.86 2275 879.26 ;
    END
  END stack_rsp_o.rdata[46]
  PIN stack_rsp_o.rdata[47]
    DIRECTION OUTPUT ;
    USE SIGNAL ;
    PORT
      LAYER Metal3 ;
        RECT  2274.6 879.7 2275 880.1 ;
    END
  END stack_rsp_o.rdata[47]
  PIN stack_rsp_o.rdata[48]
    DIRECTION OUTPUT ;
    USE SIGNAL ;
    PORT
      LAYER Metal3 ;
        RECT  2274.6 880.54 2275 880.94 ;
    END
  END stack_rsp_o.rdata[48]
  PIN stack_rsp_o.rdata[49]
    DIRECTION OUTPUT ;
    USE SIGNAL ;
    PORT
      LAYER Metal3 ;
        RECT  2274.6 881.38 2275 881.78 ;
    END
  END stack_rsp_o.rdata[49]
  PIN stack_rsp_o.rdata[4]
    DIRECTION OUTPUT ;
    USE SIGNAL ;
    PORT
      LAYER Metal3 ;
        RECT  2274.6 843.58 2275 843.98 ;
    END
  END stack_rsp_o.rdata[4]
  PIN stack_rsp_o.rdata[50]
    DIRECTION OUTPUT ;
    USE SIGNAL ;
    PORT
      LAYER Metal3 ;
        RECT  2274.6 882.22 2275 882.62 ;
    END
  END stack_rsp_o.rdata[50]
  PIN stack_rsp_o.rdata[51]
    DIRECTION OUTPUT ;
    USE SIGNAL ;
    PORT
      LAYER Metal3 ;
        RECT  2274.6 883.06 2275 883.46 ;
    END
  END stack_rsp_o.rdata[51]
  PIN stack_rsp_o.rdata[52]
    DIRECTION OUTPUT ;
    USE SIGNAL ;
    PORT
      LAYER Metal3 ;
        RECT  2274.6 883.9 2275 884.3 ;
    END
  END stack_rsp_o.rdata[52]
  PIN stack_rsp_o.rdata[53]
    DIRECTION OUTPUT ;
    USE SIGNAL ;
    PORT
      LAYER Metal3 ;
        RECT  2274.6 884.74 2275 885.14 ;
    END
  END stack_rsp_o.rdata[53]
  PIN stack_rsp_o.rdata[54]
    DIRECTION OUTPUT ;
    USE SIGNAL ;
    PORT
      LAYER Metal3 ;
        RECT  2274.6 885.58 2275 885.98 ;
    END
  END stack_rsp_o.rdata[54]
  PIN stack_rsp_o.rdata[55]
    DIRECTION OUTPUT ;
    USE SIGNAL ;
    PORT
      LAYER Metal3 ;
        RECT  2274.6 886.42 2275 886.82 ;
    END
  END stack_rsp_o.rdata[55]
  PIN stack_rsp_o.rdata[56]
    DIRECTION OUTPUT ;
    USE SIGNAL ;
    PORT
      LAYER Metal3 ;
        RECT  2274.6 887.26 2275 887.66 ;
    END
  END stack_rsp_o.rdata[56]
  PIN stack_rsp_o.rdata[57]
    DIRECTION OUTPUT ;
    USE SIGNAL ;
    PORT
      LAYER Metal3 ;
        RECT  2274.6 888.1 2275 888.5 ;
    END
  END stack_rsp_o.rdata[57]
  PIN stack_rsp_o.rdata[58]
    DIRECTION OUTPUT ;
    USE SIGNAL ;
    PORT
      LAYER Metal3 ;
        RECT  2274.6 888.94 2275 889.34 ;
    END
  END stack_rsp_o.rdata[58]
  PIN stack_rsp_o.rdata[59]
    DIRECTION OUTPUT ;
    USE SIGNAL ;
    PORT
      LAYER Metal3 ;
        RECT  2274.6 889.78 2275 890.18 ;
    END
  END stack_rsp_o.rdata[59]
  PIN stack_rsp_o.rdata[5]
    DIRECTION OUTPUT ;
    USE SIGNAL ;
    PORT
      LAYER Metal3 ;
        RECT  2274.6 844.42 2275 844.82 ;
    END
  END stack_rsp_o.rdata[5]
  PIN stack_rsp_o.rdata[60]
    DIRECTION OUTPUT ;
    USE SIGNAL ;
    PORT
      LAYER Metal3 ;
        RECT  2274.6 890.62 2275 891.02 ;
    END
  END stack_rsp_o.rdata[60]
  PIN stack_rsp_o.rdata[61]
    DIRECTION OUTPUT ;
    USE SIGNAL ;
    PORT
      LAYER Metal3 ;
        RECT  2274.6 891.46 2275 891.86 ;
    END
  END stack_rsp_o.rdata[61]
  PIN stack_rsp_o.rdata[62]
    DIRECTION OUTPUT ;
    USE SIGNAL ;
    PORT
      LAYER Metal3 ;
        RECT  2274.6 892.3 2275 892.7 ;
    END
  END stack_rsp_o.rdata[62]
  PIN stack_rsp_o.rdata[63]
    DIRECTION OUTPUT ;
    USE SIGNAL ;
    PORT
      LAYER Metal3 ;
        RECT  2274.6 893.14 2275 893.54 ;
    END
  END stack_rsp_o.rdata[63]
  PIN stack_rsp_o.rdata[6]
    DIRECTION OUTPUT ;
    USE SIGNAL ;
    PORT
      LAYER Metal3 ;
        RECT  2274.6 845.26 2275 845.66 ;
    END
  END stack_rsp_o.rdata[6]
  PIN stack_rsp_o.rdata[7]
    DIRECTION OUTPUT ;
    USE SIGNAL ;
    PORT
      LAYER Metal3 ;
        RECT  2274.6 846.1 2275 846.5 ;
    END
  END stack_rsp_o.rdata[7]
  PIN stack_rsp_o.rdata[8]
    DIRECTION OUTPUT ;
    USE SIGNAL ;
    PORT
      LAYER Metal3 ;
        RECT  2274.6 846.94 2275 847.34 ;
    END
  END stack_rsp_o.rdata[8]
  PIN stack_rsp_o.rdata[9]
    DIRECTION OUTPUT ;
    USE SIGNAL ;
    PORT
      LAYER Metal3 ;
        RECT  2274.6 847.78 2275 848.18 ;
    END
  END stack_rsp_o.rdata[9]
  PIN stack_rsp_o.valid
    DIRECTION OUTPUT ;
    USE SIGNAL ;
    PORT
      LAYER Metal3 ;
        RECT  2274.6 839.38 2275 839.78 ;
    END
  END stack_rsp_o.valid
  PIN VPWR
    DIRECTION INOUT ;
    USE POWER ;
    PORT
      LAYER TopMetal1 ;
        RECT  5.76 1024.12 2268.96 1026.12 ;
        RECT  5.76 974.12 2268.96 976.12 ;
        RECT  5.76 924.12 2268.96 926.12 ;
        RECT  5.76 874.12 2268.96 876.12 ;
        RECT  5.76 824.12 2268.96 826.12 ;
        RECT  5.76 774.12 2268.96 776.12 ;
        RECT  5.76 724.12 2268.96 726.12 ;
        RECT  5.76 674.12 2268.96 676.12 ;
        RECT  5.76 624.12 2268.96 626.12 ;
        RECT  5.76 574.12 2268.96 576.12 ;
        RECT  5.76 524.12 2268.96 526.12 ;
        RECT  5.76 474.12 2268.96 476.12 ;
        RECT  5.76 424.12 2268.96 426.12 ;
        RECT  5.76 374.12 2268.96 376.12 ;
        RECT  5.76 324.12 2268.96 326.12 ;
        RECT  5.76 274.12 2268.96 276.12 ;
        RECT  5.76 224.12 2268.96 226.12 ;
        RECT  5.76 174.12 2268.96 176.12 ;
        RECT  5.76 124.12 2268.96 126.12 ;
        RECT  5.76 74.12 2268.96 76.12 ;
        RECT  5.76 24.12 2268.96 26.12 ;
      LAYER Metal4 ;
        RECT  2265.26 14.9 2266.26 1043.5 ;
        RECT  2215.26 145.25 2216.26 908.83 ;
        RECT  2165.26 145.49 2166.26 908.59 ;
        RECT  2115.26 145.49 2116.26 908.59 ;
        RECT  2065.26 145.49 2066.26 908.59 ;
        RECT  2015.26 145.49 2016.26 908.59 ;
        RECT  1965.26 145.49 1966.26 908.59 ;
        RECT  1915.26 145.49 1916.26 908.59 ;
        RECT  1865.26 145.25 1866.26 908.83 ;
        RECT  1815.26 145.49 1816.26 908.59 ;
        RECT  1765.26 145.49 1766.26 908.59 ;
        RECT  1715.26 145.49 1716.26 908.59 ;
        RECT  1665.26 145.49 1666.26 908.59 ;
        RECT  1615.26 145.49 1616.26 908.59 ;
        RECT  1565.26 365.33 1566.26 693.07 ;
        RECT  1515.26 365.33 1516.26 693.07 ;
        RECT  1465.26 365.33 1466.26 693.07 ;
        RECT  1415.26 365.33 1416.26 693.07 ;
        RECT  1365.26 365.33 1366.26 693.07 ;
        RECT  1315.26 365.33 1316.26 693.07 ;
        RECT  1265.26 365.09 1266.26 693.31 ;
        RECT  1215.26 365.33 1216.26 693.07 ;
        RECT  1165.26 365.33 1166.26 693.07 ;
        RECT  1115.26 365.33 1116.26 693.07 ;
        RECT  1065.26 365.09 1066.26 693.31 ;
        RECT  1015.26 365.33 1016.26 693.07 ;
        RECT  965.26 365.33 966.26 693.07 ;
        RECT  915.26 365.33 916.26 693.07 ;
        RECT  865.26 365.33 866.26 693.07 ;
        RECT  815.26 365.33 816.26 693.07 ;
        RECT  765.26 365.33 766.26 693.07 ;
        RECT  715.26 365.33 716.26 693.07 ;
        RECT  665.26 365.33 666.26 693.07 ;
        RECT  615.26 365.33 616.26 693.07 ;
        RECT  565.26 365.33 566.26 693.07 ;
        RECT  515.26 365.33 516.26 693.07 ;
        RECT  465.26 365.09 466.26 693.31 ;
        RECT  415.26 365.33 416.26 693.07 ;
        RECT  365.26 365.33 366.26 693.07 ;
        RECT  315.26 365.33 316.26 693.07 ;
        RECT  265.26 365.09 266.26 693.31 ;
        RECT  215.26 365.33 216.26 693.07 ;
        RECT  165.26 365.33 166.26 693.07 ;
        RECT  115.26 365.33 116.26 693.07 ;
        RECT  65.26 365.33 66.26 693.07 ;
        RECT  15.26 365.33 16.26 693.07 ;
    END
  END VPWR
  PIN VGND
    DIRECTION INOUT ;
    USE GROUND ;
    PORT
      LAYER TopMetal1 ;
        RECT  5.76 1030.12 2269.39 1032.12 ;
        RECT  5.76 980.12 2269.39 982.12 ;
        RECT  5.76 930.12 2269.39 932.12 ;
        RECT  5.76 880.12 2269.39 882.12 ;
        RECT  5.76 830.12 2269.39 832.12 ;
        RECT  5.76 780.12 2269.39 782.12 ;
        RECT  5.76 730.12 2269.39 732.12 ;
        RECT  5.76 680.12 2269.39 682.12 ;
        RECT  5.76 630.12 2269.39 632.12 ;
        RECT  5.76 580.12 2269.39 582.12 ;
        RECT  5.76 530.12 2269.39 532.12 ;
        RECT  5.76 480.12 2269.39 482.12 ;
        RECT  5.76 430.12 2269.39 432.12 ;
        RECT  5.76 380.12 2269.39 382.12 ;
        RECT  5.76 330.12 2269.39 332.12 ;
        RECT  5.76 280.12 2269.39 282.12 ;
        RECT  5.76 230.12 2269.39 232.12 ;
        RECT  5.76 180.12 2269.39 182.12 ;
        RECT  5.76 130.12 2269.39 132.12 ;
        RECT  5.76 80.12 2269.39 82.12 ;
        RECT  5.76 30.12 2269.39 32.12 ;
      LAYER Metal4 ;
        RECT  2268.26 14.9 2269.26 1043.5 ;
        RECT  2218.26 14.9 2219.26 1043.5 ;
        RECT  2168.26 145.49 2169.26 908.59 ;
        RECT  2118.26 145.49 2119.26 908.59 ;
        RECT  2068.26 145.25 2069.26 908.83 ;
        RECT  2018.26 145.49 2019.26 908.59 ;
        RECT  1968.26 145.49 1969.26 908.59 ;
        RECT  1918.26 145.49 1919.26 908.59 ;
        RECT  1868.26 145.49 1869.26 908.59 ;
        RECT  1818.26 145.49 1819.26 908.59 ;
        RECT  1768.26 145.49 1769.26 908.59 ;
        RECT  1718.26 145.49 1719.26 908.59 ;
        RECT  1668.26 145.25 1669.26 908.83 ;
        RECT  1618.26 145.25 1619.26 908.83 ;
        RECT  1568.26 365.09 1569.26 693.31 ;
        RECT  1518.26 365.09 1519.26 693.31 ;
        RECT  1468.26 365.33 1469.26 693.07 ;
        RECT  1418.26 365.33 1419.26 693.07 ;
        RECT  1368.26 365.33 1369.26 693.07 ;
        RECT  1318.26 365.33 1319.26 693.07 ;
        RECT  1268.26 365.33 1269.26 693.07 ;
        RECT  1218.26 365.33 1219.26 693.07 ;
        RECT  1168.26 365.33 1169.26 693.07 ;
        RECT  1118.26 365.33 1119.26 693.07 ;
        RECT  1068.26 365.33 1069.26 693.07 ;
        RECT  1018.26 365.33 1019.26 693.07 ;
        RECT  968.26 365.33 969.26 693.07 ;
        RECT  918.26 365.33 919.26 693.07 ;
        RECT  868.26 365.09 869.26 693.31 ;
        RECT  818.26 365.09 819.26 693.31 ;
        RECT  768.26 365.09 769.26 693.31 ;
        RECT  718.26 365.09 719.26 693.31 ;
        RECT  668.26 365.33 669.26 693.07 ;
        RECT  618.26 365.33 619.26 693.07 ;
        RECT  568.26 365.33 569.26 693.07 ;
        RECT  518.26 365.33 519.26 693.07 ;
        RECT  468.26 365.33 469.26 693.07 ;
        RECT  418.26 365.33 419.26 693.07 ;
        RECT  368.26 365.33 369.26 693.07 ;
        RECT  318.26 365.33 319.26 693.07 ;
        RECT  268.26 365.33 269.26 693.07 ;
        RECT  218.26 365.33 219.26 693.07 ;
        RECT  168.26 365.33 169.26 693.07 ;
        RECT  118.26 365.33 119.26 693.07 ;
        RECT  68.26 365.09 69.26 693.31 ;
        RECT  18.26 365.09 19.26 693.31 ;
    END
  END VGND
  OBS
    LAYER Metal1 ;
     RECT  0 0 2275 1061.84 ;
    LAYER Metal2 ;
     RECT  0 0 2275 1061.84 ;
    LAYER Metal3 ;
     RECT  0 0 2275 1061.84 ;
    LAYER Metal4 ;
     RECT  0 0 2275 1061.84 ;
    LAYER TopMetal1 ;
     RECT  0 0 2275 1061.84 ;
  END
END ino_data_cache
END LIBRARY
